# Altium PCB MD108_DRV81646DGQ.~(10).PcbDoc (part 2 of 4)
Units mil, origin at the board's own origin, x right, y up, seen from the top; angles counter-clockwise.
Board outline 6002 x 2931.52 mil, 4 copper layers (Top Layer, Mid-Layer 1, Mid-Layer 2, Bottom Layer), stack 92.712 mil thick; 255 components, 141 nets, 784 pads, 239 vias.
Unrouted connection lines stored in the file: 111.

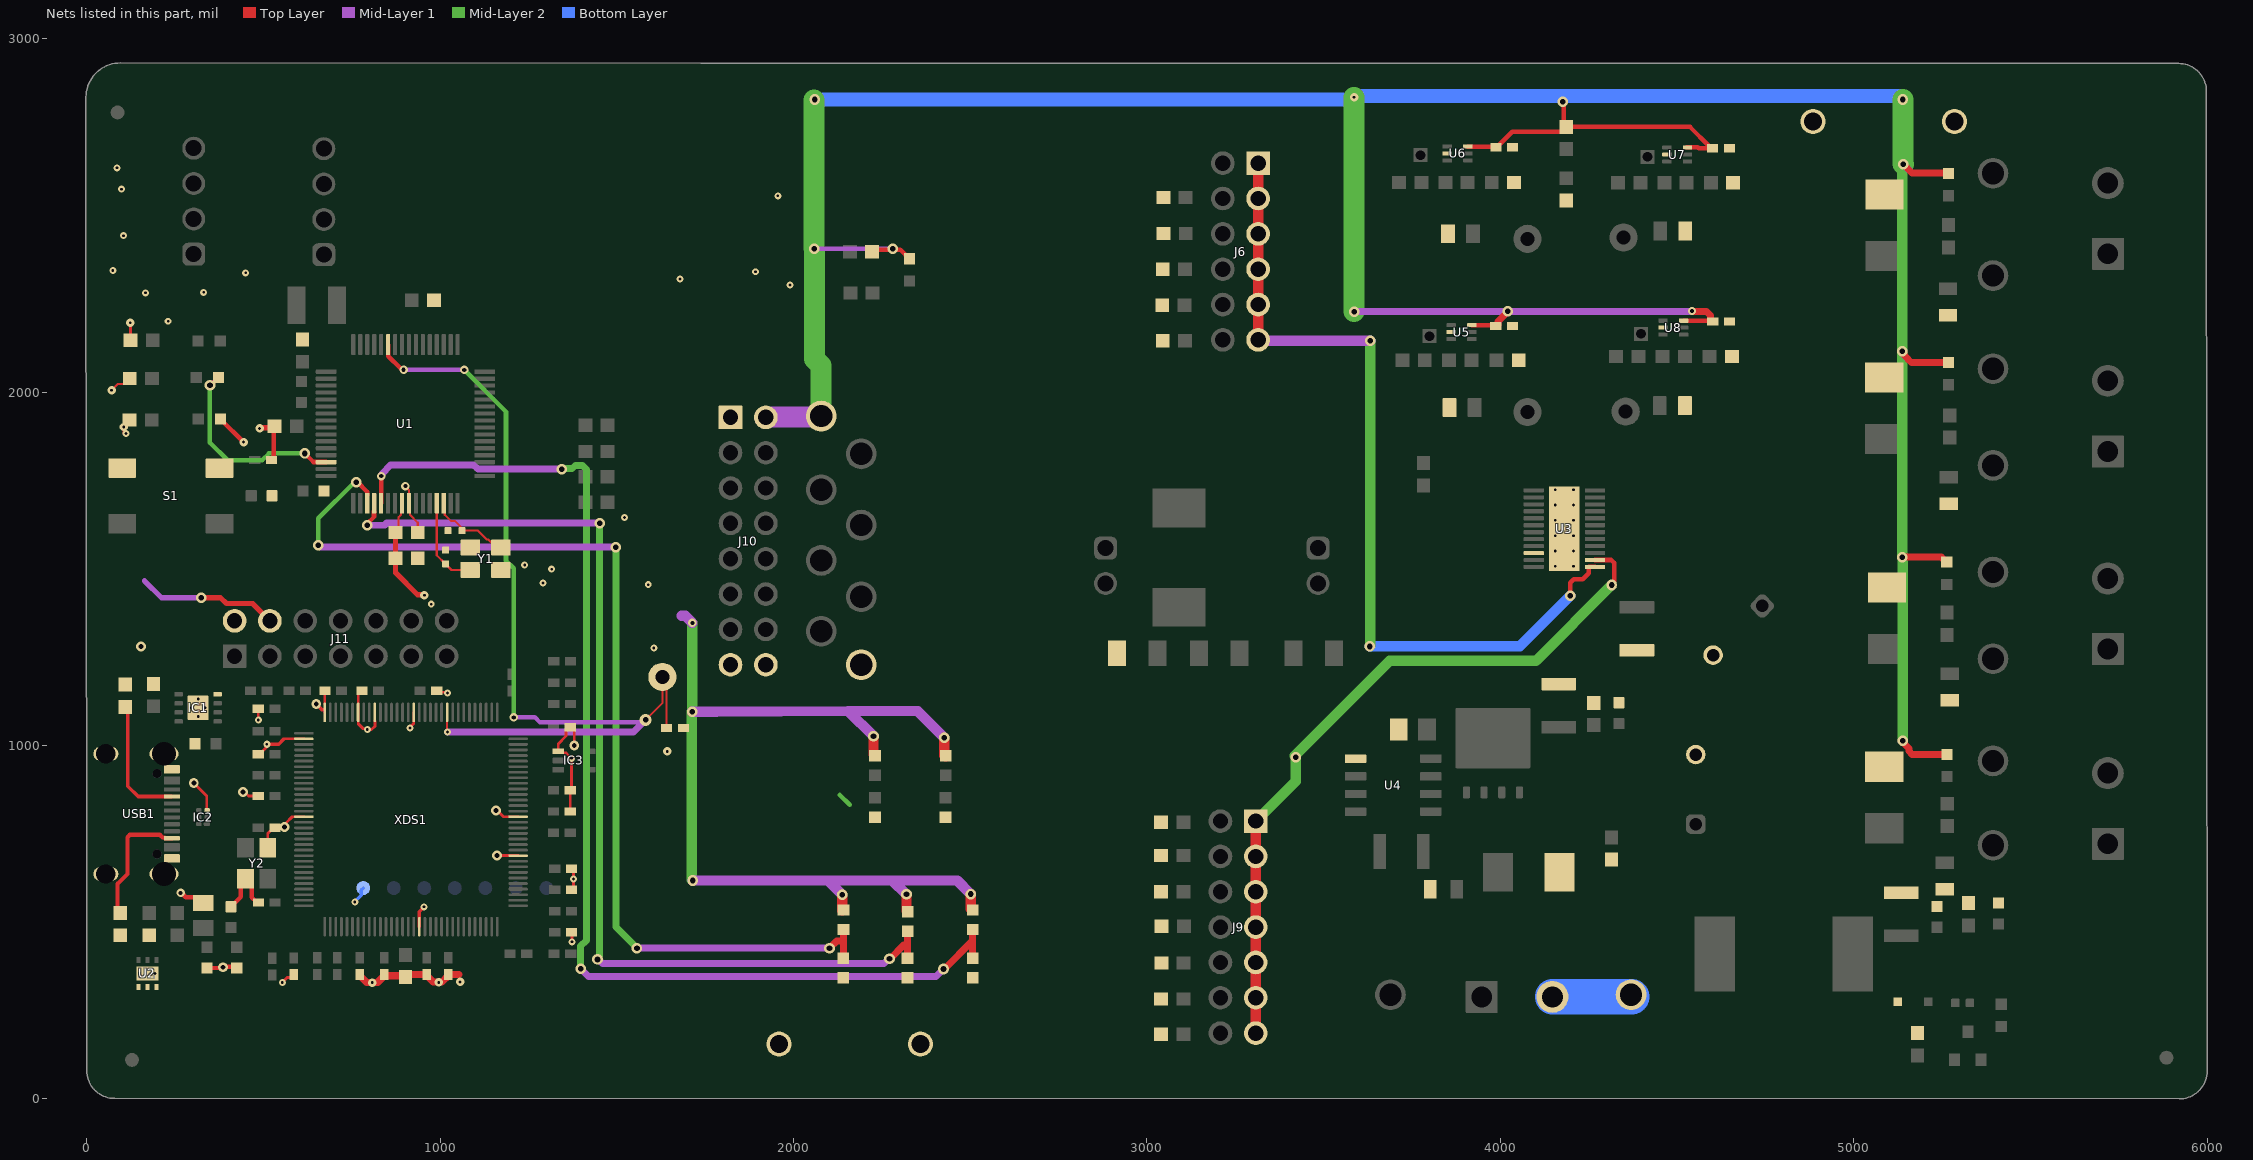
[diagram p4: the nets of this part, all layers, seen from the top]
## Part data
C1: library part CMP-0120896-1, "1 µF ±10% 50V Ceramic Capacitor X7R 0603 (1608 Metric)", Digikey Part Number=732-885012206126CT-ND, Manufacturer="Wurth Electronics", Mouser Part Number=710-885012206126, Operating Temperature Range="-55°C to +125°C", TempCo=15%, Temperature Characteristic=X7R, Tolerance_%=10%, ValueDisplayed=1uF
C2: library part CMP-0120893-1, "10000 pF ±10% 25V Ceramic Capacitor X7R 0603 (1608 Metric)", Digikey Part Number=732-7983-1-ND, Manufacturer="Wurth Electronics", Mouser Part Number=710-885012206065, Operating Temperature Range="-55°C to +125°C", TempCo=15%, Temperature Characteristic=X7R, Tolerance_%=10%, ValueDisplayed=10nF
C3: library part CMP-0119380-1, "WCAP-CSGP Multilayer Ceramic Chip Capacitor, General Purpose, size 0603, X7R Class II, 470nF, 25VDC", Capacitance Tolerance=+/-10%, Case/Size Code=0603, Insulation Resistance=1.1GOhm, Manufacturer="Wurth Elektronik", Operating Temperature Max=125°C, Operating Temperature Min=-55°C, Rated Voltage (DC)=25V
C4: library part CMP-0006837-4, "CAP, CERM, 0.1 uF, 50 V, +/- 10%, X7R, 0603", Cap_Case=0603, Manufacturer="Wurth Elektronik", TempCo=X7R, Tolerance_%=10%, Value1=Unknown, Value2=50V, ValueDisplayed=0.1uF
C5: library part CMP-0860569-1, "CAP, CERM, 10 µF, 25 V,+/- 10%, X5R, 0603", Cap_Case=0603, Manufacturer=MuRata, TempCo=X5R, Tolerance_%=10%, Value2=25V, ValueDisplayed=10µF
C6 C7: library part CMP-0120892-1, "22 pF ±5% 50V Ceramic Capacitor C0G, NP0 0402 (1005 Metric)", Digikey Part Number=732-7471-1-ND, Manufacturer="Wurth Electronics", Mouser Part Number=710-885012005057, Operating Temperature Range="-55°C to +125°C", TempCo=30ppm/°C, Temperature Characteristic=NP0, Tolerance_%=5%, ValueDisplayed=22pF
C8 C12 C17 C20 C24 C25 C28: library part CMP-0006623-2, "CAP, CERM, 0.1 uF, 6.3 V, +/- 10%, X7R, 0402", Cap_Case=0402, Manufacturer=MuRata, Supplier Part Number 1=GRM155R70J104KA01D-ND, TempCo=X7R, Tolerance_%=10%, Value1=Unknown, Value2=6.3V, ValueDisplayed=0.1uF
C9 C10 C11 C15 C18: library part CMP-0006658-2, "CAP, CERM, 0.01 uF, 25 V, +/- 10%, X7R, 0402", Cap_Case=0402, Manufacturer=MuRata, Supplier Part Number 1=490-1312-1-ND, TempCo=X7R, Tolerance_%=10%, Value1=Unknown, Value2=25V, ValueDisplayed=0.01uF
C13: library part CMP-0006831-4, "CAP, CERM, 1 uF, 16 V, +/- 10%, X7R, 0603", Cap_Case=0603, Manufacturer="Wurth Elektronik", Supplier Part Number 1=710-885012206052, TempCo=X7R, Tolerance_%=10%, Value1=Unknown, Value2=16V, ValueDisplayed=1uF
C14: library part CMP-0078154-1, "CAP, CERM, 10 µF, 16 V,+/- 20%, X5R, 0805", Cap_Case=0805, Manufacturer="Wurth Elektronik", Supplier Part Number 1=732-7624-1-ND, TempCo=X5R, Tolerance_%=20%, Value2=16V, ValueDisplayed=10µF
C16 C23: library part CMP-0006415-2, "CAP, CERM, 12 pF, 50 V, +/- 5%, C0G/NP0, 0402", Cap_Case=0402, Manufacturer=MuRata, Supplier Part Number 1=14T3292, TempCo=C0G/NP0, Tolerance_%=5%, Value1=Unknown, Value2=50V, ValueDisplayed=12pF
C19 C26 C29: library part CMP-0006276-2, "CAP, CERM, 1 uF, 25 V, +/- 10%, X5R, 0402", Cap_Case=0402, Manufacturer=TDK, Supplier Part Number 1=445-9066-1-ND, TempCo=X5R, Tolerance_%=10%, Value1=Unknown, Value2=25V, ValueDisplayed=1uF
C21: library part CMP-0750039-1, "CAP, CERM, 0.01 µF, 50 V,+/- 10%, X7R, 0603", Cap_Case=0603, Manufacturer="Wurth Elektronik", TempCo=X7R, Tolerance_%=10%, Value2=50V, ValueDisplayed=0.01µF
C22: library part CMP-0049204-1, "0.1 µF ±10% 50V Ceramic Capacitor X7R 0603 (1608 Metric)", Digikey Part Number=732-8013-1-ND, Manufacturer=Wurth, Mouser Part Number=710-885012206095, Operating Temperature Range="-55°C to +125°C", TempCo=15%, Temperature Characteristic=X7R, Tolerance_%=10%, ValueDisplayed=100nF
C27: library part CMP-0006906-5, "CAP, CERM, 2.2 uF, 10 V, +/- 10%, X5R, 0603", Cap_Case=0603, Manufacturer=Kemet, Supplier Part Number 1=399-4911-1-ND, TempCo=X5R, Tolerance_%=10%, Value1=Unknown, Value2=10V, ValueDisplayed=2.2uF
C30: library part CMP-0119330-1, "WCAP-CSGP Multilayer Ceramic Chip Capacitor, General Purpose, size 0603, X7R, 2.2µF, 10VDC", Capacitance Tolerance=+/-10%, Case/Size Code=0603, Insulation Resistance=0.02GOhm, Manufacturer="Wurth Elektronik", Operating Temperature Max=125°C, Operating Temperature Min=-55°C, Rated Voltage (DC)=10V
C31 C33 C35 C37: library part CMP-0006829-4, "CAP, CERM, 0.1 uF, 16 V, +/- 10%, X7R, 0603", Cap_Case=0603, Manufacturer="Wurth Elektronik", Supplier Part Number 1=710-885012206046, TempCo=X7R, Tolerance_%=10%, Value1=Unknown, Value2=16V, ValueDisplayed=0.1uF
C32 C34 C36 C38: library part CMP-0006219-2, "CAP, CERM, 0.1 uF, 6.3 V, +/- 20%, X5R, 0402", Cap_Case=0402, Manufacturer="Wurth Elektronik", Supplier Part Number 1=732-7478-1-ND, TempCo=X5R, Tolerance_%=20%, Value1=Unknown, Value2=6.3V, ValueDisplayed=0.1uF
C39: library part CMP-0102580-1, "WCAP-ATUL Aluminum Electrolytic Capacitor, Radial, THT, D10 x H12.5mm, 47µF, 100V", Capacitance Tolerance=20%, Leakage Current=47uA, Manufacturer="Wurth Elektronik", Operating Temperature Max=105°C, Operating Temperature Min=-40°C, Rated Voltage (DC)=100V, Ripple Current=400mA
C40 C41 C46: library part CMP-0097312-1, "1 µF ±10% 100V Ceramic Capacitor X7R 1210 (3225 Metric)", Manufacturer="Wurth Electronics", Operating Temperature Range="-55°C to +125°C", TempCo=15%, Temperature Characteristic=X7R, Tolerance_%=10%, ValueDisplayed=1uF
C42 C48: library part CMP-0079993-1, "CAP, CERM, 0.01 µF, 100 V,+/- 10%, X7R, 0603", Cap_Case=0603, Manufacturer="Wurth Elektronik", Supplier Part Number 1=45AC8565, TempCo=X7R, Tolerance_%=10%, Value2=100V, ValueDisplayed=0.01µF
C43: library part CMP-0102582-1, "WCAP-ATUL Aluminum Electrolytic Capacitor, Radial, THT, D10 x H20mm, 82µF, 100V", Capacitance Tolerance=20%, Leakage Current=82uA, Manufacturer="Wurth Elektronik", Operating Temperature Max=105°C, Operating Temperature Min=-40°C, Rated Voltage (DC)=100V, Ripple Current=600mA
C44 C49: library part CMP-0097294-1, "0.1 µF ±10% 100V Ceramic Capacitor X7R 0603 (1608 Metric)", Digikey Part Number=732-885012206120TR-ND, Manufacturer="Wurth Electronics", Mouser Part Number=710-885012206120, Operating Temperature Range="-55°C to +125°C", TempCo=15%, Temperature Characteristic=X7R, Tolerance_%=10%, ValueDisplayed=100nF
C45: library part CMP-0006724-5, "CAP, CERM, 1000 pF, 100 V, +/- 10%, X7R, 0603", Cap_Case=0603, Manufacturer=AVX, Supplier Part Number 1=478-1199-1-ND, TempCo=X7R, Tolerance_%=10%, Value1="0.276 ohm", Value2=100V, ValueDisplayed=1000pF
C47 C53 C54 C55 C56: library part CMP-0119538-1, "WCAP-CSGP Multilayer Ceramic Chip Capacitor, General Purpose, size 0805, X7R, 22nF, 100VDC", Capacitance Tolerance=+/-10%, Case/Size Code=0805, Insulation Resistance=4.5GOhm, Manufacturer="Wurth Elektronik", Operating Temperature Max=125°C, Operating Temperature Min=-55°C, Rated Voltage (DC)=100V
C50: library part CMP-0119409-1, "WCAP-CSGP Multilayer Ceramic Chip Capacitor, General Purpose, size 0603, X7R, 1nF, 100VDC", Capacitance Tolerance=+/-10%, Case/Size Code=0603, Insulation Resistance=10GOhm, Manufacturer="Wurth Elektronik", Operating Temperature Max=125°C, Operating Temperature Min=-55°C, Rated Voltage (DC)=100V
C51: library part CMP-0119921-1, "WCAP-CSST Multilayer Ceramic Chip Capacitor, Soft Termination, size 1210, X7R Class II, 2.2µF, 100VDC", Capacitance Tolerance=+/-10%, Case/Size Code=1210, Insulation Resistance=0.05GOhm, Manufacturer="Wurth Elektronik", Operating Temperature Max=125°C, Operating Temperature Min=-55°C, Rated Voltage (DC)=100V
C52: library part CMP-0007891-2, "CAP, CERM, 1 uF, 100 V, +/- 10%, X7S, 0805", Cap_Case=0805, Manufacturer=TDK, Supplier Part Number 1=445-5205-1-ND, TempCo=X7S, Tolerance_%=10%, Value1="0.008255 ohm", Value2=100V, ValueDisplayed=1uF
D1 D2 D3 D13 D14 D15 D16 D18: library part CMP-0002894-2, "LED, Green, SMD", Color=green, Manufacturer="Wurth Elektronik", Value1=W, Value2=2V
D4: library part CMP-0078131-2, "LED, Red, SMD", Color=Red, Manufacturer=Lite-On, Power_TotalModule=62.5mW, Value1=.0625W, Value2=2V
D5: library part CMP-0002827-3, "LED, Green, SMD", Color=green, Manufacturer=Lite-On, Power_TotalModule=100mW, Value1=0.1W, Value2=2.1V
D6: library part CMP-0002947-3, "LED, Red, SMD", Color=Red, Manufacturer="Wurth Elektronik", Power_TotalModule=72mW, Value1=0.072W, Value2=2V
D7: library part CMP-0005695-3, "Diode, TVS, Bi, 33 V, SMC", Manufacturer=Bourns, Value1=1500W
D8: library part CMP-0005587-3, "Diode, TVS, Bi, 70 V, SMB", Manufacturer="Diodes Inc.", Value1=600W
D9 D10 D11 D12: library part CMP-0005564-3, "Diode, TVS, Bi, 33 V, SMB", Manufacturer="Diodes Inc.", Value1=600W
D17: library part CMP-14400-000003-2, "DIODE ZENER 4.7V 550MW SOD323F"
FID1 FID2 FID3: library part CMP-0077181-1, "Fiducial mark.  There is nothing to buy or mount.", Manufacturer=N/A
IC1: library part CMP-0036329-3, "500mA, Adjustable, Low Quiescent Current, Low-Noise, High-PSRR, Single-Output LDO Regulator, DRB0008A (VSON-8)", Manufacturer="Texas Instruments", Operating Temperature Range="-40 to 125 C", Rating=Catalog
IC2: library part CMP-0043115-3, "4-Channel ESD Protection Array for High-Speed Data Interfaces, DRY0006A (USON-6)", Breakdown Voltage(Min)(V)=6, IO Capacitance(Typ)(pF)=1.6, IO Leakage Current(nA)=1, Manufacturer="Texas Instruments", Operating Temperature Range="-40 to 85 C", Rating=Catalog
IC3: library part CMP-0032790-2, "Precision Micropower Shunt Voltage Reference, 0.5% accuracy, 2.5 V, 15 ppm / degC, 15 mA, -40 to 85 degC, 5-pin SC70 (DCK), Green (RoHS & no Sb/Br)", Manufacturer="Texas Instruments", Rating=Catalog, Temp Coeff(Max)(ppm/ degree C)=100, Temp Coeff(Typ)(ppm/ degree C)=15
J1 J2 J3 J4 J5: library part CMP-0121282-1, "2 Position Wire to Board Terminal Block Horizontal with Board 0.200\" (5.08mm) Through Hole", Current_A=20A, Digikey Part Number=732-10995-ND, Manufacturer="Wurth Electronics", Mouser Part Number=710-691236510002, Operating Temperature Range="-30°C to +120°C", Voltage_V=300V
J6: library part CMP-0092423-1, "THT Vertical Pin Header WR-PHD, Pitch 2.54 mm, Dual Row, 12 pins", Current_A=3A, Digikey Part Number=732-5297-ND, Manufacturer="Wurth Electronics", Mouser Part Number=710-61301221121, Operating Temperature Range="-40°C to +105°C", Voltage_V=250V
J7 J8: library part CMP-0054794-2, "Header, 2.54 mm, 2x1, Gold, TH", Color=Black, Manufacturer="Wurth Elektronik", Supplier Part Number 1=732-5315-ND
J9 J11: library part CMP-0097334-1, "Connector Header Through Hole 14 position 0.100\" (2.54mm)", Current_A=3A, Digikey Part Number=732-5298-ND, Manufacturer="Wurth Electronics", Mouser Part Number=710-61301421121, Operating Temperature Range="-40°C to +105°C", Voltage_V=250V
J10: library part CMP-0125672-1, "Connector Header Through Hole 16 position 0.100\" (2.54mm)", Current_A=3A, Digikey Part Number=732-5299-ND, Manufacturer=Wurth, Mouser Part Number=710-61301621121, Operating Temperature Range="-40°C to +105°C", Voltage_V=250V
J12 J13: library part CMP-0054798-2, "Header, 2.54 mm, 4x1, Gold, TH", Color=Black, Manufacturer="Wurth Elektronik", Supplier Part Number 1=732-5317-ND
L1: library part CMP-0063986-1, "Inductor, Shielded Drum Core, Ferrite, 1 uH, 24 A, 0.0012 ohm, SMD", Manufacturer="Wurth Elektronik", Supplier Part Number 1=732-2138-1-ND, Value1="0.0012 ohm", Value2=24A, ValueDisplayed=1uH
L3: library part CMP-0003267-2, "Ferrite Bead, 600 ohm @ 100 MHz, 0.5 A, 0603", Manufacturer="Wurth Elektronik", Supplier Part Number 1=732-2389-1-ND, Value1="0.35 ohm", Value2=0.5A, ValueDisplayed=600Ω
Logo1: library part CMP-0074844-2, Manufacturer="Texas Instruments"
Logo2: library part CMP-0074838-1, "Texas Instrument Corporate Signature"
Logo3: library part CMP-0074847-1, "FCC_disclaimer"
Logo4: library part CMP-0074769-4, Manufacturer="Texas Instruments"
LOGO5: library part CMP-0074837-2, "IEC 61010-1 Hot Surface Warning", Manufacturer="Texas Instruments"
Logo6: library part CMP-0074836-1, "IEC 61010-1 Caution Warning"
MP1 MP2 MP3 MP4: library part CMP-0122650-1, "Bumper Cylindrical, Dome 0.720\" Dia (18.30mm) Polyurethane Black", Digikey Part Number=RPC4835-ND, Manufacturer="Essentra Components", Mouser Part Number=144-RBS-37BK, Operating Temperature Range="32°F to 122°F"
Q2: library part CMP-1048-00779-1, "General Purpose Transistor, NPN Silicon, 3-Pin SOT-23, Pb-Free, Tape and Reel", Manufacturer="On Semiconductor"
Q4: library part CMP-0000915-2, "MOSFET, N-CH, 80 V, 100 A, DNK0008A (VSON-CLIP-8)", Alternate Manufacturer=None, Manufacturer="Texas Instruments", Supplier Part Number 1=296-37194-1-ND, Value2="48 nC"
R1 R2 R3 R34: library part CMP-0025912-5, "RES, 330, 5%, 0.1 W, 0603", Manufacturer=Yageo, Power_W=100mW, Supplier Part Number 1=311-330GRCT-ND, TempCo="100 ppm/C", Tolerance_%=5%, Value2=0.1W, Value_Code=330R, ValueDisplayed=330
R4: library part CMP-0083496-1, "RES, 20 k, 5%, 0.5 W, 1210", Manufacturer=Yageo, Power_W=500mW, TempCo="100 ppm/C", Tolerance_%=5%, Value2=0.5W, Value_Code=20k0, ValueDisplayed=20k
R5: library part CMP-0025899-5, "RES, 1.0 k, 5%, 0.1 W, 0603", Manufacturer=Yageo, Power_W=100mW, Supplier Part Number 1=311-1.0KGRCT-ND, TempCo="100 ppm/C", Tolerance_%=5%, Value2=0.1W, Value_Code=1k00, ValueDisplayed=1.0k
R6 R7: library part CMP-0025885-5, "RES, 0, 5%, 0.1 W, 0603", Manufacturer=Yageo, PartNumber=RC0603JR-070RL, Power_W=100mW, Supplier Part Number 1=311-0.0GRCT-ND, TempCo="200 ppm/C", Tolerance_%=5%, Value2=0.1W, Value_Code=0000, ValueDisplayed=0
R8 R32: library part CMP-0026935-3, "RES, 47 k, 5%, 0.063 W, AEC-Q200 Grade 0, 0402", Manufacturer=Vishay-Dale, Power_W=63mW, Supplier Part Number 1=541-47KJCT-ND, TempCo="200 ppm/C", Tolerance_%=5%, Value2=0.063W, Value_Code=47k0, ValueDisplayed=47k
R9: library part CMP-0025875-3, "RES, 100 k, 5%, 0.1 W, AEC-Q200 Grade 0, 0603", Manufacturer=Panasonic, Power_W=100mW, Supplier Part Number 1=P100KGCT-ND, TempCo="200 ppm/C", Tolerance_%=5%, Value2=0.1W, Value_Code=100k
R10: library part CMP-0022941-4, "RES, 249 k, 1%, 0.1 W, 0603", Manufacturer=Yageo, Power_W=100mW, Supplier Part Number 1=311-249KHRCT-ND, TempCo="100 ppm/C", Tolerance_%=1%, Value2=0.1W, Value_Code=249k
R11: library part CMP-0023118-5, "RES, 44.2 k, 1%, 0.1 W, 0603", Manufacturer=Yageo, Power_W=100mW, Supplier Part Number 1=311-44.2KHRCT-ND, TempCo="100 ppm/C", Tolerance_%=1%, Value2=0.1W, Value_Code=44k2, ValueDisplayed=44.2k
R12: library part CMP-0022804-5, "RES, 14.0 k, 1%, 0.1 W, 0603", Manufacturer=Yageo, Power_W=100mW, Supplier Part Number 1=311-14.0KHRCT-ND, TempCo="100 ppm/C", Tolerance_%=1%, Value2=0.1W, Value_Code=14k0, ValueDisplayed=14.0k
R13 R23: library part CMP-0025932-5, "RES, 5.1 k, 5%, 0.1 W, 0603", Manufacturer=Yageo, Power_W=100mW, Supplier Part Number 1=311-5.1KGRCT-ND, TempCo="100 ppm/C", Tolerance_%=5%, Value2=0.1W, Value_Code=5k10, ValueDisplayed=5.1k
R14 R25 R26: library part CMP-0026825-5, "RES, 10 k, 5%, 0.063 W, AEC-Q200 Grade 0, 0402", Manufacturer=Vishay-Dale, Power_W=63mW, Supplier Part Number 1=541-10KJCT-ND, TempCo="200 ppm/C", Tolerance_%=5%, Value2=0.063W, Value_Code=10k0, ValueDisplayed=10k
R15 R24: library part CMP-0026824-3, "RES, 100, 5%, 0.063 W, AEC-Q200 Grade 0, 0402", Manufacturer=Vishay-Dale, Power_W=63mW, Supplier Part Number 1=541-100JCT-ND, TempCo="200 ppm/C", Tolerance_%=5%, Value2=0.063W, Value_Code=100R, ValueDisplayed=100
R16: library part CMP-0026413-2, "RES, 4.87 k, 1%, 0.063 W, AEC-Q200 Grade 0, 0402", Manufacturer=Vishay-Dale, Power_W=63mW, Supplier Part Number 1=541-4.87KLCT-ND, TempCo="100 ppm/C", Tolerance_%=1%, Value2=0.063W, Value_Code=4k87, ValueDisplayed=4.87k
R17: library part CMP-0026695-1, "RES, 3.30 k, 1%, 0.1 W, AEC-Q200 Grade 0, 0402", Manufacturer=Panasonic, Power_W=100mW, Supplier Part Number 1=P3.30KLCT-ND, TempCo="100 ppm/C", Tolerance_%=1%, Value2=0.1W, Value_Code=3k30, ValueDisplayed=3.30k
R18 R19 R20 R21 R28: library part CMP-0026852-3, "RES, 1.0 k, 5%, 0.063 W, AEC-Q200 Grade 0, 0402", Manufacturer=Vishay-Dale, Power_W=63mW, Supplier Part Number 1=541-1.0KJCT-ND, TempCo="200 ppm/C", Tolerance_%=5%, Value2=0.063W, Value_Code=1k00, ValueDisplayed=1.0k
R22: library part CMP-0026946-3, "RES, 51, 5%, 0.063 W, AEC-Q200 Grade 0, 0402", Manufacturer=Vishay-Dale, Power_W=63mW, Supplier Part Number 1=541-51JCT-ND, TempCo="200 ppm/C", Tolerance_%=5%, Value2=0.063W, Value_Code=51R0, ValueDisplayed=51
R27 R31: library part CMP-0026934-3, "RES, 470, 5%, 0.063 W, AEC-Q200 Grade 0, 0402", Manufacturer=Vishay-Dale, Power_W=63mW, Supplier Part Number 1=541-470JCT-ND, TempCo="200 ppm/C", Tolerance_%=5%, Value2=0.063W, Value_Code=470R, ValueDisplayed=470
R29: library part CMP-0026731-1, "RES, 330 k, 1%, 0.0625 W, 0402", Manufacturer="Yageo America", Power_W=62.5mW, Supplier Part Number 1=311-330KLRCT-ND, TempCo="100 ppm/C", Tolerance_%=1%, Value2=0.0625W, Value_Code=330k
R30: library part CMP-0026728-1, "RES, 220 k, 1%, 0.0625 W, 0402", Manufacturer="Yageo America", Power_W=62.5mW, Supplier Part Number 1=311-220KLRCT-ND, TempCo="100 ppm/C", Tolerance_%=1%, Value2=0.0625W, Value_Code=220k
R33: library part CMP-0023155-5, "RES, 4.99 k, 1%, 0.1 W, 0603", Manufacturer=Yageo, Power_W=100mW, Supplier Part Number 1=311-4.99KHRCT-ND, TempCo="100 ppm/C", Tolerance_%=1%, Value2=0.1W, Value_Code=4k99, ValueDisplayed=4.99k
R35 R36 R37 R38 R39 R40 R41 R42 R43 R44: library part CMP-0025886-5, "RES, 10 k, 5%, 0.1 W, 0603", Manufacturer=Yageo, Power_W=100mW, Supplier Part Number 1=311-10KGRCT-ND, TempCo="100 ppm/C", Tolerance_%=5%, Value2=0.1W, Value_Code=10k0, ValueDisplayed=10k
R45 R53 R74: library part CMP-0022746-5, "RES, 10.0 k, 1%, 0.1 W, 0603", Manufacturer=Yageo, Power_W=100mW, Supplier Part Number 1=311-10.0KHRCT-ND, TempCo="100 ppm/C", Tolerance_%=1%, Value2=0.1W, Value_Code=10k0, ValueDisplayed=10.0k
R46 R56: library part CMP-0023212-5, "RES, 60.4 k, 1%, 0.1 W, 0603", Manufacturer=Yageo, Power_W=100mW, Supplier Part Number 1=311-60.4KHRCT-ND, TempCo="100 ppm/C", Tolerance_%=1%, Value2=0.1W, Value_Code=60k4, ValueDisplayed=60.4k
R47 R58: library part CMP-0022768-4, "RES, 120 k, 1%, 0.1 W, 0603", Manufacturer=Yageo, Power_W=100mW, Supplier Part Number 1=311-120KHRCT-ND, TempCo="100 ppm/C", Tolerance_%=1%, Value2=0.1W, Value_Code=120k
R48: library part CMP-0022844-4, "RES, 180 k, 1%, 0.1 W, 0603", Manufacturer=Yageo, Power_W=100mW, Supplier Part Number 1=311-180KHRCT-ND, TempCo="100 ppm/C", Tolerance_%=1%, Value2=0.1W, Value_Code=180k
R49 R59: library part CMP-0022937-4, "RES, 240 k, 1%, 0.1 W, 0603", Manufacturer=Yageo, Power_W=100mW, Supplier Part Number 1=311-240KHRCT-ND, TempCo="100 ppm/C", Tolerance_%=1%, Value2=0.1W, Value_Code=240k
R50 R51 R52: library part CMP-0086176-1, "RES, 0, 0.75 W, AEC-Q200 Grade 0, 1206", Manufacturer=Vishay-Dale, Power_W=750mW, Tolerance_%=0%, Value2=0.75W, Value_Code=0
R54: library part CMP-0023020-5, "RES, 30.0 k, 1%, 0.1 W, 0603", Manufacturer=Yageo, Power_W=100mW, Supplier Part Number 1=311-30.0KHRCT-ND, TempCo="100 ppm/C", Tolerance_%=1%, Value2=0.1W, Value_Code=30k0, ValueDisplayed=30.0k
R55: library part CMP-0023098-5, "RES, 40.2 k, 1%, 0.1 W, 0603", Manufacturer=Yageo, Power_W=100mW, Supplier Part Number 1=311-40.2KHRCT-ND, TempCo="100 ppm/C", Tolerance_%=1%, Value2=0.1W, Value_Code=40k2, ValueDisplayed=40.2k
R57: library part CMP-0023285-5, "RES, 80.6 k, 1%, 0.1 W, 0603", Manufacturer=Yageo, Power_W=100mW, Supplier Part Number 1=311-80.6KHRCT-ND, TempCo="100 ppm/C", Tolerance_%=1%, Value2=0.1W, Value_Code=80k6, ValueDisplayed=80.6k
R60 R61 R65 R66 R68 R69 R71 R72: library part CMP-0025874-4, "RES, 0, 5%, 0.1 W, AEC-Q200 Grade 0, 0603", Manufacturer=Panasonic, Power_W=100mW, Supplier Part Number 1=P0.0GCT-ND, TempCo="600 ppm/C", Tolerance_%=5%, Value2=0.1W, Value_Code=0000, ValueDisplayed=0
R62 R67 R70 R73: library part CMP-0041688-1, "10 mOhms ±1% 0.5W, 1/2W Chip Resistor 0805 (2012 Metric) Current Sense Thick Film", Digikey Part Number=732-13830-1-ND, Manufacturer="Wurth Electronics", Mouser Part Number=710-580060720008, Operating Temperature Range="-55°C to +155°C", Power_W=500mW, TempCo=100ppm/°C, Tolerance_%=1%
R63 R64: library part CMP-0022902-5, "RES, 200, 1%, 0.1 W, 0603", Manufacturer=Yageo, Power_W=100mW, Supplier Part Number 1=311-200HRCT-ND, TempCo="100 ppm/C", Tolerance_%=1%, Value2=0.1W, Value_Code=200R, ValueDisplayed=200
R77 R78 R79 R80: library part CMP-0025922-5, "RES, 430, 5%, 0.1 W, 0603", Manufacturer=Yageo, Power_W=100mW, Supplier Part Number 1=311-430GRCT-ND, TempCo="100 ppm/C", Tolerance_%=5%, Value2=0.1W, Value_Code=430R, ValueDisplayed=430
R81: library part CMP-0097568-1, "47 kOhms ±1% 0.125W, 1/8W Chip Resistor 0402 (1005 Metric) Automotive AEC-Q200 Thick Film", Digikey Part Number=541-RCC040247K0FKEDCT-ND, Manufacturer="Vishay Dale", Mouser Part Number=71-RCC040247K0FKED, Operating Temperature Range="-55°C to +155°C", Power_W=125mW, TempCo=100ppm/°C, Tolerance_%=1%
R82: library part CMP-0023129-5, "RES, 470, 1%, 0.1 W, 0603", Manufacturer=Yageo, Power_W=100mW, Supplier Part Number 1=311-470HRCT-ND, TempCo="100 ppm/C", Tolerance_%=1%, Value2=0.1W, Value_Code=470R, ValueDisplayed=470
S1: library part CMP-0097347-1, "Tactile Switch SPST-NO Top Actuated Surface Mount", Coil Resistance_ohm=100mΩ, Contact Current Rating=50mA, Digikey Part Number=732-7022-1-ND, Manufacturer="Wurth Electronics", Mouser Part Number=710-430481025816, Operating Force=160gf, Operating Temperature Range="-40°C to +85°C"
SH1 SH2: library part CMP-0075110-1, "1mm Uninsulated Shorting Plug, 10.16mm spacing, TH", Manufacturer=Harwin, PartNumber=D3082-05, Supplier Part Number 1=952-1873-ND
SH-J1 SH-J2 SH-J3 SH-J4 SH-J5 SH-J6 SH-J7 SH-J8 SH-J9 SH-J10 SH-J11 SH-J12 SH-J14 SH-J15 SH-J16 SH-J17 SH-J18 SH-J19 SH-J20: library part CMP-0003761-2, "Shunt, 2.54mm, Gold, Black", Manufacturer="Wurth Elektronik", Supplier Part Number 1=732-2678-ND
TP1 TP2 TP3 TP4 TP5 TP6 TP7: library part CMP-0003825-1, "1mm Test Point, SMT", Manufacturer=Any, PartNumber=TP_SM_1MM
TP8 TP24 TP27 TP28 TP29: library part CMP-0055139-2, "Test Point, Miniature, White, TH", Color=White, Manufacturer="Keystone Electronics", Supplier Part Number 1=36-5002-ND
TP9 TP11 TP12 TP13 TP14 TP15 TP17 TP18 TP19 TP22: library part CMP-0055149-2, "Test Point, Multipurpose, White, TH", Color=White, Manufacturer="Keystone Electronics", Supplier Part Number 1=36-5012-ND
TP10: library part CMP-0055150-1, "Test Point, Multipurpose, Orange, TH", Color=Orange, Manufacturer=Keystone, Supplier Part Number 1=36-5013-ND
TP16 TP21 TP23 TP31 TP32: library part CMP-0055147-2, "Test Point, Multipurpose, Red, TH", Color=Red, Manufacturer="Keystone Electronics", Supplier Part Number 1=36-5010-ND
TP25: library part CMP-0055148-2, "Test Point, Multipurpose, Black, TH", Color=Black, Manufacturer="Keystone Electronics", Supplier Part Number 1=36-5011-ND
TP33: library part CMP-0055148-1, "Test Point, Multipurpose, Black, TH", Color=Black, Manufacturer=Keystone, Supplier Part Number 1=36-5011-ND
U1: library part CMP-0093960-1, "Mixed-Signal Microcontrollers With CAN-FD Interface LQFP64", Frequency_Fixed=80MHz, Manufacturer="Texas Instruments", Max Supply Voltage=3.6V, Min Supply Voltage=1.62V, Operating Temperature Range="-40°C to +125°C"
U2: library part CMP-0077837-1, "5-V Precision Surge Protection Clamp, DRV0006A (WSON-6)", Alternate Manufacturer="Texas Instruments"
U3: library part CMP-0125014-1, "Quad Low-Side Switches, HVSSOP24", Manufacturer="Texas Instruments", Max Supply Voltage=65V, Min Supply Voltage=4.5V, Nominal Supply Current=3mA, Operating Temperature Range="-40°C to +150°C"
U4: library part CMP-0125797-1, Manufacturer="Texas Instruments", Operating Temperature Range=to
U5 U6 U7 U8: library part CMP-0085241-1, "Bidirectional, Precision Low- and High-Side Voltage Output, Current-Sense Amplifier, DRL0006A (SOT-5X3-6)", Alternate Manufacturer="Texas Instruments", Alternate PartNumber=INA185A2IDRLR
USB1: library part CMP-0095999-2, "Conenctor USB 2.0 Type C Horizontal SMT", Current_A=5A, Manufacturer="Wurth Electronics", Operating Temperature Range="-40°C to +85°C", Voltage_V=20V
XDS1: library part CMP-0077954-1, "MSP432E401YTPDT, PDT0128A (TQFP-128)", Alternate Manufacturer="Texas Instruments", Alternate PartNumber=MSP432E401YTPDT
Y1: library part CMP-0098168-2, "Crystal 40MHz ±10ppm (Tol) ±20ppm (Stability) 12pF FUND 40Ohm 4-Pin Mini-CSMD T/R", Frequency Stability=20ppm, Frequency Tolerance=10ppm, Frequency_Fixed=40MHz, Load Capacitance=12pF, Manufacturer="Seiko Epson", Operating Temperature Range="-40°C to +105°C"
Y2: library part CMP-0004635-3, "Crystal, 16 MHz, 8pF, SMD", Frequency Stability=+/-30ppm, Frequency_Fixed=16MHz, Manufacturer=NDK, Supplier Part Number 1=644-1157-1-ND
ZZ1: library part CMP-0003616-3
ZZ2: library part CMP-0077236-1
ZZ3: library part CMP-0077237-1
ZZ4: library part CMP-0077238-1

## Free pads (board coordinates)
  rect 39.37x39.37 hole 27.56: 3(4398.45,2164.95) 7(3773.88,2670.35) 7(3799.96,2158.3) 7(4416.63,2665.76)

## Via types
v1: diameter 30, hole 16, Top Layer to Bottom Layer, tented both sides, 89 vias
v2: diameter 20, hole 8, Top Layer to Bottom Layer, tented both sides, 47 vias
v3: diameter 19.68, hole 7.87, Top Layer to Bottom Layer, tented both sides, 35 vias
v4: diameter 24, hole 12, Top Layer to Bottom Layer, tented both sides, 14 vias
v5: diameter 24, hole 7.87, Top Layer to Bottom Layer, tented both sides, 11 vias
v6: diameter 30, hole 15, Top Layer to Bottom Layer, tented both sides, 10 vias
v7: diameter 28, hole 14, Top Layer to Bottom Layer, tented both sides, 9 vias
v8: diameter 19.68, hole 7.87, Top Layer to Bottom Layer, 6 vias
v9: diameter 24, hole 8, Top Layer to Bottom Layer, tented both sides, 5 vias
v10: diameter 30, hole 14, Top Layer to Bottom Layer, tented both sides, 4 vias
v11: diameter 24, hole 11.81, Top Layer to Bottom Layer, tented both sides, 4 vias
v12: diameter 36, hole 18.29, Top Layer to Bottom Layer, tented both sides, 2 vias
v13: diameter 30, hole 15.75, Top Layer to Bottom Layer, tented both sides, 2 vias
v14: diameter 34, hole 16, Top Layer to Bottom Layer, tented both sides, 1 vias

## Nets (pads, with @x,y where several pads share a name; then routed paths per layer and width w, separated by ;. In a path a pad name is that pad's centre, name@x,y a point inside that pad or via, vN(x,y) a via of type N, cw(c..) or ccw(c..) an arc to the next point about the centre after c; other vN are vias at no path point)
3V3: C32.2 C34.2 C36.2 C38.2 D6.2 D13.2 D14.2 D15.2 D16.2 J10.2 R33.2 R63.2 TP10.1 U5.6 U6.6 U7.6 U8.6 | length 9611.1
  Top Layer w12.83: R33.2@2215.65,2401.97 2216.41,2402.74 2277.57,2402.74 v1(2280.86,2406.02) 2284.14,2402.74 2302.6,2402.74 2327.64,2377.69 D6.2@2331.23,2377.69 ; U6.6@3908.06,2694.9 3908.57,2694.38 C32.2@3983.59,2694.38 ; U5.6@3919.44,2189.5 3919.95,2188.99 C36.2@3985.12,2188.99 ; C32.2@3983.59,2694.58 3993.41,2694.58 3996.77,2697.94 3996.77,2699.76 4034.07,2737.06 4174.21,2737.06 4186.49,2749.34 R63.2@4186.49,2750.33 4536.98,2750.33 4591.53,2695.77 4591.53,2694.96 C34.2@4596.93,2689.56 ; v1(4176.98,2822.09) 4179.12,2819.95 R63.2@4179.12,2756.36 ; U8.6@4518.83,2202.04 4519.35,2201.53 C38.2@4593.47,2201.53 ; U7.6@4528.09,2692.81 4558.19,2692.81 4561.44,2689.56 C34.2@4596.93,2689.56 ; C34.2@4604.01,2687.37 4599.13,2687.37 C34.2@4596.93,2689.56
  Top Layer w19.68: C36.2@3986.25,2187.33 3991.1,2187.33 3992.9,2189.13 3992.9,2199.38 4020.71,2227.18 v1(4020.71,2228.35) ; v4(4542.46,2229.48) 4543.29,2228.65 4583.66,2228.65 4595.19,2217.12 4595.19,2201.66 4597.16,2199.69 C38.2@4601.09,2199.69 ; v1(5137.37,2115.28) 5137.37,2110.61 5154.18,2093.8 5154.18,2092.86 5163.19,2083.85 D14.2@5268.21,2083.85 ; v1(5137.66,1532.96) 5247.87,1532.96 5252.59,1528.25 5254.12,1528.25 5261.97,1520.4 D15.2@5261.97,1518.87 ; v1(5138.92,1013.35) 5138.92,1008.71 5156.17,991.46 5156.17,984.09 5165.25,975.01 D16.2@5264.42,975.01 ; v1(5140.47,2644.7) 5165.42,2619.76 5265.14,2619.76 D13.2@5266.14,2620.76
  Top Layer w59.06: J10.2@1918.99,1928.64 1920.52,1928.64 J10.2@1922.46,1926.71
  Mid-Layer 1 w12.83: v1(2058.25,2406.02) v1(2280.86,2406.02)
  Mid-Layer 1 w19.68: v1(3586.44,2227.8) 3586.71,2228.07 v1@4019.12,2228.07 ; v1(4020.71,2228.35) 4541.33,2228.35 v4(4542.46,2229.48)
  Mid-Layer 1 w59.06: J10.2@1918.99,1928.64 1920.36,1930.01 2076.04,1930.01 TP10.1@2078.24,1932.21
  Mid-Layer 2 w29.53: v1(5138.92,1013.35) 5138.92,1531.57 5137.66,1532.84 5137.66,2114.86 5137.37,2115.15 5137.37,2641.47 5140.47,2644.57 v1(5140.47,2644.7)
  Mid-Layer 2 w59.06: v1@2057.96,2826.86 2058.25,2826.57 v1(2058.25,2406.02) 2059.56,2404.71 2059.56,2093.82 2078.24,2075.14 TP10.1@2078.24,1932.21 ; v1(3586.44,2227.8) v9(3586.44,2834.36) ; v1(5139.28,2828.08) 5139.28,2645.9 v1(5140.47,2644.7)
  Bottom Layer w19.68: v1(3586.44,2227.8) v1@3586.71,2228.07 ; v1@4020.44,2228.07 v1(4020.71,2228.35)
  Bottom Layer w39.37: v1(2060.1,2828.08) 3580.16,2828.08 v9(3586.44,2834.36) ; v9@3586.44,2837.84 5129.52,2837.84 v1(5139.28,2828.08)
3V3_MCU: C4.1 C5.1 D3.2 J10.1 J11.4 R7.1 R8.2 R35.1 R37.1 R39.1 R41.1 R43.1 U1.40 | length 3720
  Top Layer w6: C4.1@873.83,1602.89 882.61,1611.68 882.61,1646.01 889.31,1652.7 889.31,1655.55 889.31,1682.69 U1.40@892.21,1685.59
  Top Layer w12.83: D3.2@378.52,1923.54 444.42,1857.63 v5@444.42,1857.37 ; R8.2@522.58,1808.03 523.69,1808.03 529.09,1813.43 R7.1@529.09,1902.65
  Top Layer w15: v6(323.86,1418.2) 378.73,1418.2 395.36,1401.57 469.61,1401.57 J11.4@518.44,1352.72 ; v5(489.23,1897.18) 490.95,1898.9 525.1,1898.9 R7.1@528.85,1902.65 ; C4.1@873.83,1602.89 873.83,1489.04 936.15,1426.72 953.88,1426.72 v5(955.6,1425)
  Top Layer w29.53: v1(2137.5,577.9) 2138.38,577.03 R39.1@2138.38,534.3 ; v1(2226.44,1026.09) 2226.44,975.52 R35.1@2228.19,973.77 ; R41.1@2319.74,532.56 v1(2319.74,578.77) ; v1(2427,1021.73) 2427,972.9 R37.1@2430.48,969.41 ; v1(2501.99,579.64) 2501.99,537.79 R43.1@2504.6,535.17
  Mid-Layer 1 w15: 163.76,1465.84 211.39,1418.2 v6(323.86,1418.2)
  Mid-Layer 1 w29.53: 1684.15,1367.17 1693.49,1367.17 v11(1713.95,1346.71) ; v1(1713.71,1095.38) 1781.13,1095.38 1781.7,1095.95 2154.94,1097.59 ; v1(1714.6,618.01) 2098.27,618.01 ; v1(2137.5,577.9) 2136.63,578.77 2136.63,579.64 2098.27,618.01 ; v1(2226.44,1026.09) 2154.94,1097.59 ; v1(2319.74,578.77) 2318.87,578.77 2279.63,618.01 ; v1(2427,1021.73) 2351.14,1097.59 2154.94,1097.59 ; v1(2501.99,579.64) 2463.62,618.01 2279.63,618.01 ; 2098.27,618.01 2279.63,618.01
  Mid-Layer 2 w29.53: v1@1712.57,1095.38 1712.57,619.46 v1@1714.28,617.74 ; v1(1713.71,1095.38) 1713.71,1346.47 v11(1713.95,1346.71)
  other v5: 443.72,1858.75
+5V: J11.2
BSL_INVOKE: R32.2 TP8.1 U1.11 XDS1.42 | length 2613.7
  Top Layer w6: XDS1.42@1019.98,1093.72 1019.98,1038.93 v3(1020.64,1038.27) ; v14(1581.77,1072.7) 1629,1119.92 TP8.1@1629,1194 1641,1182 R32.2@1641.01,1049.62
  Top Layer w12.83: U1.11@852.84,2134.41 853.35,2133.9 853.35,2101.73 888.29,2066.79 889.78,2066.79 893.51,2063.06 v4(896.54,2063.06)
  Mid-Layer 1 w6: v14@1581.22,1072.14 v14@1581.22,1074.06
  Mid-Layer 1 w12.83: v4(896.54,2063.06) 1068.13,2063.06 v4(1068.32,2062.87) ; v4(1208.2,1079.48) 1268.4,1079.48 1282.73,1065.15 1568.5,1065.15 1580.98,1077.63 v14@1583.08,1077.63
  Mid-Layer 1 w19.68: v3(1020.64,1038.27) 1547.35,1038.27 v14@1581.22,1072.14
  Mid-Layer 2 w12.83: v4(1068.32,2062.87) 1186.44,1944.74 1186.44,1522.99 1208.2,1501.23 v4(1208.2,1079.48)
CC1: R13.1 USB1.A5 | length 364.1
  Top Layer w10: R13.1@108.91,1109.14 116.59,1101.45 116.59,884.67 145.6,855.67 USB1.A5@241.04,855.67
CC2: R23.1 USB1.B5 | length 362.2
  Top Layer w12: R23.1@94.73,526.06 86.91,533.89 86.91,608.51 115.09,636.69 115.09,740.38 122.12,747.41 206.51,747.41 214.57,739.34 220.21,739.34 221.89,737.66 240.94,737.66 USB1.B5@241.04,737.56
COD/INRUSH: J6.1 J6.3 J6.5 J6.7 J6.9 J6.11 U3.13 | length 2454.8
  Top Layer w12.83: v1(4197.75,1423.32) 4197.75,1460.49 4207.86,1470.61 4233.28,1470.61 4250.13,1487.46 4250.13,1504.74 4250.64,1505.25 U3.13@4267.92,1505.25
  Top Layer w29.53: J6.1@3311.87,2655.3 3314.82,2652.34 J6.1@3314.82,2647.78 J6.11@3314.82,2147.78
  Mid-Layer 1 w29.53: J6.11@3314.82,2147.78 3317.02,2145.58 v1(3632.19,2145.58)
  Mid-Layer 2 w29.53: v1(3630.96,1280.32) 3632.19,1281.56 v1(3632.19,2145.58)
  Bottom Layer w29.53: v1(3630.96,1280.32) 4054.75,1280.32 v1(4197.75,1423.32)
DEV_ID1: R39.2 R40.1 U1.35 | length 2948.7
  Top Layer w12.83: v1(762.87,1745.3) 765,1743.16 768.38,1743.16 793.27,1718.27 U1.35@793.27,1708.7
  Top Layer w19.68: v1(2101.99,426.78) 2122.37,447.16 2141.07,447.16 ; R40.1@2139.91,403.7 2141.07,404.87 2141.07,447.16 ; R39.2@2141.22,479.06 2141.07,478.92 2141.07,447.16
  Mid-Layer 1 w19.68: v1(655.45,1566.92) 656.61,1566.92 661.36,1562.17 1496.33,1562.17 v1(1497.14,1561.36) ; v1(1556.99,426.78) v1(2101.99,426.78)
  Mid-Layer 2 w12.83: v1(655.45,1566.92) 655.45,1642.68 756.32,1743.55 761.12,1743.55 v1(762.87,1745.3)
  Mid-Layer 2 w19.68: v1(1497.14,1561.36) 1497.14,486.63 v1(1556.99,426.78)
DEV_ID2: R41.2 R42.1 U1.36 | length 2922.5
  Top Layer w12.83: v1(794.15,1623.23) 794.15,1627.87 812.96,1646.68 U1.36@812.96,1662.48
  Top Layer w19.68: v1(2271.64,396.32) 2273.32,396.32 2313.19,436.19 2323.12,436.19 ; R42.1@2320.74,400.83 2323.12,403.22 2323.12,436.19 ; R41.2@2323.2,474.53 2323.12,474.45 2323.12,436.19
  Mid-Layer 1 w19.68: v1(794.15,1623.23) 842.77,1623.23 848.52,1628.97 1451.24,1628.97 v1(1451.34,1629.07) ; v1(1445.25,394.67) 1448.04,394.67 1459.04,383.68 2256.21,383.68 2268.85,396.32 v1(2271.64,396.32)
  Mid-Layer 2 w19.68: v1(1445.25,394.67) 1445.25,397.46 1451.34,403.55 v1(1451.34,1629.07)
DEV_ID3: R43.2 R44.1 U1.37 | length 3335.6
  Top Layer w12.83: U1.37@833.16,1685.59 v4(833.16,1762.34)
  Top Layer w19.68: v1(2424.34,367.55) 2427.04,367.55 2506.99,447.5 ; R43.2@2506.99,479.06 2506.99,447.5 ; R44.1@2511.41,407.8 2507.51,407.8 2506.99,408.32 2506.99,447.5
  Mid-Layer 1 w19.68: v4@835.1,1768.61 860.02,1793.53 1095.04,1793.53 1106.77,1781.8 v1(1344.58,1781.8) ; v1(1397.67,368.52) 1420.25,345.94 2402.73,345.94 v1(2424.34,367.55)
  Mid-Layer 2 w19.68: v1(1344.58,1781.8) 1346.56,1783.78 1373.81,1783.78 1382.73,1792.7 1402.42,1792.7 1413.95,1781.17 1413.95,448.36 1397.67,432.08 v1(1397.67,368.52)
GND: C2.2 C3.1 C4.2 C5.2 C6.1 C7.1 C8.2 C9.2 C10.2 C11.2 C12.2 C13.2 C14.2 C15.2 C16.2 C17.2 C18.2 C19.2 C20.2 C21.2 C22.2 C23.2 C24.2 C25.2 C26.2 C27.2 C28.2 C29.2 C30.1 C32.1 C34.1 C36.1 C38.1 C39.2 C40.1 C41.1 C42.1 C43.2 C44.1 C45.2 C46.1 C47.1 C48.1 C49.1 C50.1 C52.2 C53.1 C54.1 C55.1 C56.1 D4.2 D5.2 D8.1 D9.1 D10.1 D11.1 D12.1 D17.2 IC1.4 IC1.9 IC2.3 IC3.1 J5.2 J10.15 J10.16 R1.1 R2.1 R3.1 R5.1 R6.1 R13.2 R16.1 R23.2 R30.1 R32.1 R36.2 R38.2 R40.2 R42.2 R44.2 R45.1 R46.1 R47.1 R48.1 R49.1 R50.1 R53.1 R54.1 R55.1 R56.1 R57.1 R58.1 R59.1 R61.1 R62.1 R64.1 R66.1 R67.1 R69.1 R70.1 R72.1 R73.1 R82.1 S1.3 S1.4 SH1.1 SH1.2 SH2.1 SH2.2 TP1.1 TP25.1 TP33.1 U1.41 U2.1 U2.2 U2.3 U2.7@171.8,354.86 U3.10 U3.25 U4.1 U5.2 U6.2 U7.2 U8.2 USB1.1 USB1.2 USB1.3 USB1.4 USB1.A1-B12 USB1.A12-B1 XDS1.10 XDS1.17 XDS1.48 XDS1.55 XDS1.58 XDS1.64 XDS1.66 XDS1.80 XDS1.114 Y1.2 Y1.4 Y2.2 Y2.4 | length 2790
  Top Layer w6: v5(70.4,2005.1) 88.08,2022.78 106.03,2022.78 R2.1@121.73,2038.49 ; v4(901.85,1734.24) 901.85,1732.46 911.9,1722.41 U1.41@911.9,1685.59 914.8,1682.69 914.8,1652.62 936.83,1630.59 C4.2@936.83,1602.89 ; R32.1@1684.32,1049.62 R32.1@1688.25,1049.62
  Top Layer w8: v3@104.72,1883.17 v9(104.72,1901.23) 121.04,1917.55 R3.1@121.04,1921.12 ; R1.1@122.75,2145.6 R1.1@123.8,2146.65 123.51,2146.94 v5(123.51,2196.26) ; v7(303.01,893.72) 339.86,856.88 339.86,820.06 340.3,819.62 IC2.3@338.33,819.62 ; v7(442.61,868.57) 446.24,868.57 457.63,857.18 C15.2@485.37,857.18 ; C8.2@483.18,1103.54 485.61,1101.11 v2(485.61,1072.57) ; C12.2@485.37,975.59 489.31,975.59 507.32,993.6 507.32,1001.27 v2(509.61,1003.57) v2@507.32,1005.86 ; Y2.2@512.19,710.19 512.19,750.75 528.68,767.24 C16.2@532.62,767.24 533.45,768.07 559.19,768.07 v7(560.02,768.9) 563.85,772.72 563.85,780.8 581.49,798.44 XDS1.80@614.46,798.44 ; v2(553.48,329.8) 567.56,343.87 578.02,343.87 585.83,351.68 C24.2@585.83,351.79 ; 557.61,1018.57 557.96,1018.91 XDS1.66@614.46,1018.91 ; XDS1.64@673.52,1093.72 XDS1.64@673.52,1101.49 ; XDS1.64@673.52,1117.28 R16.1@673.52,1154.45 ; C9.2@777.24,1160.69 776.27,1160.69 768.46,1152.88 768.46,1069.64 768.52,1069.58 768.52,1061.66 782.65,1047.53 791.8,1047.53 v2(794.1,1045.23) 794.15,1045.28 806.33,1045.28 815.71,1054.66 815.71,1069.77 XDS1.55@815.32,1070.16 ; v2(914.8,1049.28) 914.8,1051.45 925.49,1062.13 XDS1.48@925.49,1093.72 ; C10.2@990.44,1154.97 994.55,1150.86 1018.32,1150.86 v2(1020.61,1148.57) ; v7@1160.65,688.53 XDS1.10@1221.18,688.53 ; v7@1161.83,815.57 1178.96,798.44 XDS1.17@1220.76,798.44 ; C18.2@1368.35,813.04 C17.2@1368.35,873 1371.81,876.46 v2(1371.81,963.72) 1356.25,979.28 1338.2,979.28 IC3.1@1334.32,983.16 1334.32,1004.24 1356.61,1026.53 1356.61,1043.74 1364.42,1051.55 C11.2@1368.35,1051.55 1371.8,1051.55 1379.61,1043.74 v7(1379.61,1000.57) ; R30.1@1371.81,471.51 1373.61,469.71 v2(1373.61,444.57) ; C20.2@1371.81,591.43 1377.61,597.24 v2(1377.61,622.57) 1377.61,645.58 C19.2@1371.81,651.39
  Top Layer w10: v2(509.61,1003.57) 543.32,1003.57 557.97,1018.21 ; v7(649.61,1117.57) 665.69,1101.49 XDS1.64@672.46,1101.49 ; XDS1.114@941.24,487.42 941.24,529.98 954.61,543.35 v2(954.61,543.57) ; v7(1158.61,815.57) v7@1161.83,815.57
  Top Layer w12: D4.2@344.61,368.07 346.86,370.32 383.37,370.32 v7(385.61,372.57) 387.31,374.26 422.92,374.26 D5.2@424.61,375.96
  Top Layer w12.83: v4(265.77,582.98) 268.79,582.98 280.69,571.08 316.6,571.08 C14.2@328.88,558.79 ; C22.2@408.25,543.9 435.73,571.38 435.73,619.34 Y2.4@444.58,628.19 ; Y2.4@449.2,623.58 466.4,606.37 466.4,571.09 481.8,555.69 C23.2@486.7,555.69
  Top Layer w20: C25.2@773.12,352.34 773.12,348.4 791.64,329.89 807.25,329.89 v9(808.01,329.12) 808.78,329.89 823.49,329.89 842,348.4 C26.2@842,352.34 842,350.21 843.81,348.4 898.41,348.4 C27.2@902.34,344.46 ; C27.2@902.34,352.34 C28.2@962.68,352.34 962.68,348.4 980.52,330.56 995.17,330.56 v9(995.94,329.8) 996.7,330.56 1005.19,330.56 1023.03,348.4 C29.2@1023.03,352.34 1053.13,352.34 1053.89,351.57
  Mid-Layer 2 w12.83: 2131.08,859.9 2158.7,832.28
  Bottom Layer w10: v2(758.61,557.57) 776.99,575.95 776.99,590.95 TP1.1@782.61,596.57
  Bottom Layer w100: J5.2@4147.5,288.7 4371.68,288.7 TP25.1@4371.89,288.91
  other v3: 1604.86,1275.57 974.91,1399.99 1588.97,1454.95 1291.33,1459.84 1315.83,1499 4155.72,1507.22 4206.9,1507.22 1239.32,1510.87 4155.72,1550.53 4206.9,1550.53 4155.72,1593.83 4206.9,1593.83 4155.72,1637.14 4206.9,1637.14 1521.78,1645.19 4155.72,1680.45 4206.9,1680.45 4155.72,1723.76 4206.9,1723.76 110.99,1883.17 230.52,2200.49 166.13,2280.94 331.06,2282.41 1990.01,2303.33 1679.19,2320.24 449.92,2337.53 1892.48,2340.6 73.8,2344.2 103.92,2442.58 1955.65,2555.47 98.86,2574.08 85.9,2634.57
  other v5: 1642.59,983.19
  other v7: 1160.61,688.57 153.24,1280.43
  other v8: 150.14,354.86 193.45,354.86 315.39,1081.98 295.7,1106.58 335.07,1106.58 315.39,1131.19
  other v9: 1056.77,331.16
GUI_STATUS: D2.2 U1.30 | length 561.8
  Top Layer w12.83: v1(348.81,2018.99) 351.02,2018.99 370.87,2038.85 D2.2@372.59,2038.85 ; v1(617.39,1826.47) 641.61,1802.24 677.13,1802.24 U1.30@677.64,1801.73
  Mid-Layer 2 w12.83: v1(348.81,2018.99) 348.81,1857.18 399.07,1806.92 496.14,1806.92 515.68,1826.47 v1(617.39,1826.47)
HFXIN: C7.2 U1.45 Y1.3 | length 259.5
  Top Layer w6: U1.45@990.64,1685.59 990.64,1538.51 C7.2@1015.46,1513.68 1032.38,1496.76 1085.21,1496.76 Y1.3@1085.61,1497.16
HFXOUT: C6.2 U1.46 Y1.1 | length 231.4
  Top Layer w6: U1.46@1010.32,1685.59 1013.23,1682.69 1013.23,1652.7 1030.36,1635.57 1041.79,1635.57 1069.46,1607.9 1107.24,1607.9 1132.66,1582.48 1136.95,1582.48 1159.27,1560.15 Y1.1@1172.22,1560.15
ILIM: J9.1 J9.3 J9.5 J9.7 J9.9 J9.11 J9.13 U3.14 | length 2051.1
  Top Layer w12.83: U3.14@4267.92,1524.94 4314.31,1524.94 4321.82,1517.42 4321.82,1464.85 4313.73,1456.76 v1@4313.73,1452.74
  Top Layer w29.53: J9.1@3304.36,785.4 3308.12,781.65 J9.9@3308.12,386.13 J9.11@3308.12,286.13 J9.13@3308.12,186.13
  Mid-Layer 2 w29.53: J9.1@3308.12,786.13 3420.92,898.93 v1(3420.92,966.72) ; v1@3418.18,970.72 3686.92,1239.46 4101.08,1239.46 v1(4315.83,1454.21)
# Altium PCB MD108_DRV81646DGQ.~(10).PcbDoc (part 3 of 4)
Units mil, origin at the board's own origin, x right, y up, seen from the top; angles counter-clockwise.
Board outline 6002 x 2931.52 mil, 4 copper layers (Top Layer, Mid-Layer 1, Mid-Layer 2, Bottom Layer), stack 92.712 mil thick; 255 components, 141 nets, 784 pads, 239 vias.
Unrouted connection lines stored in the file: 111.

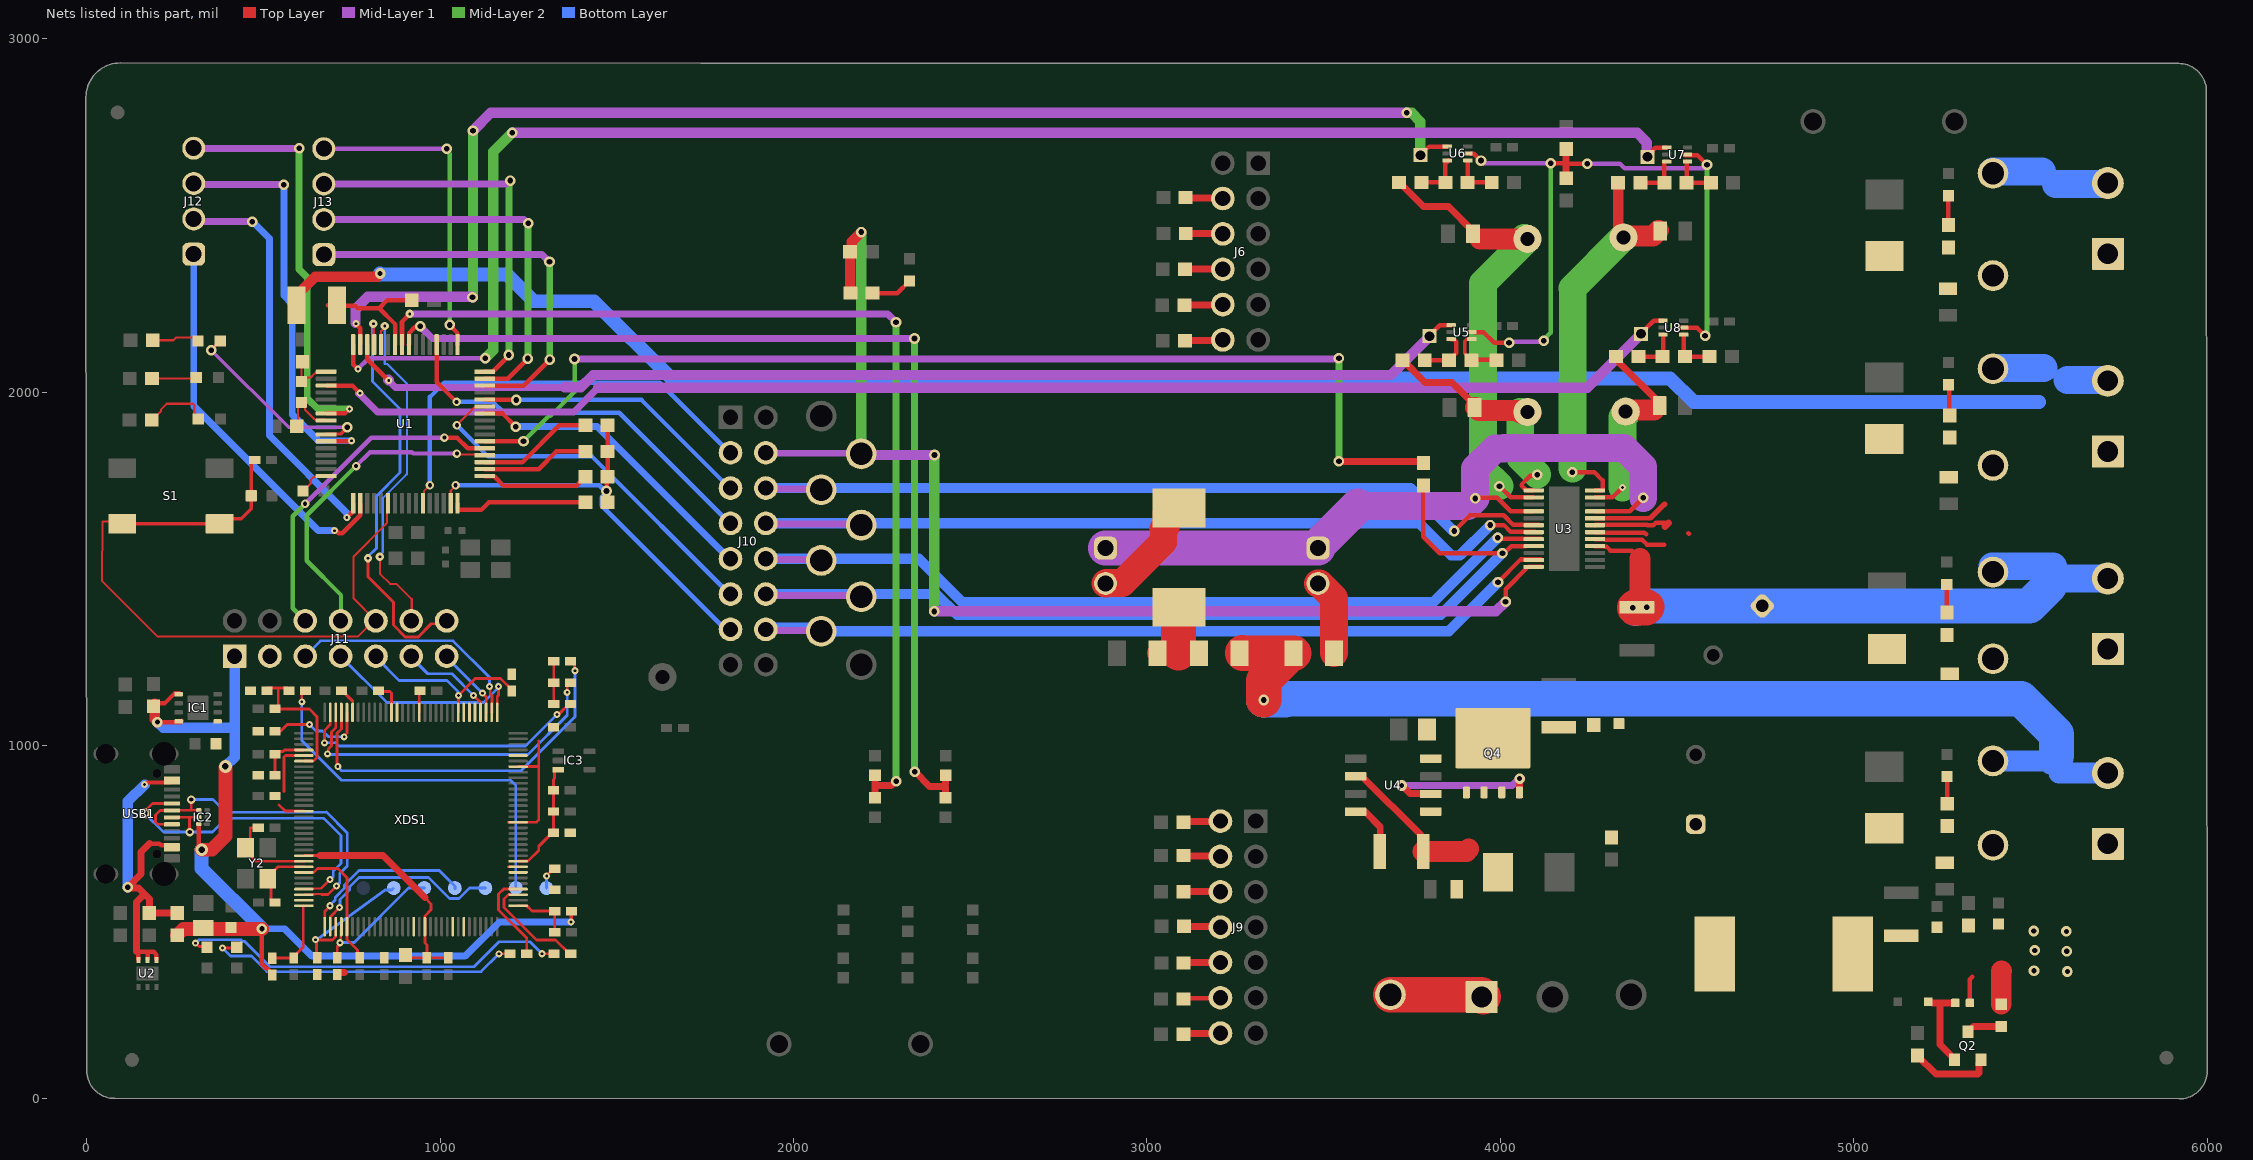
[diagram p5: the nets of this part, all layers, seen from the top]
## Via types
v1: diameter 30, hole 16, Top Layer to Bottom Layer, tented both sides, 89 vias
v2: diameter 20, hole 8, Top Layer to Bottom Layer, tented both sides, 47 vias
v3: diameter 19.68, hole 7.87, Top Layer to Bottom Layer, tented both sides, 35 vias
v4: diameter 24, hole 12, Top Layer to Bottom Layer, tented both sides, 14 vias
v5: diameter 24, hole 7.87, Top Layer to Bottom Layer, tented both sides, 11 vias
v6: diameter 30, hole 15, Top Layer to Bottom Layer, tented both sides, 10 vias
v7: diameter 28, hole 14, Top Layer to Bottom Layer, tented both sides, 9 vias
v8: diameter 19.68, hole 7.87, Top Layer to Bottom Layer, 6 vias
v9: diameter 24, hole 8, Top Layer to Bottom Layer, tented both sides, 5 vias
v10: diameter 30, hole 14, Top Layer to Bottom Layer, tented both sides, 4 vias
v11: diameter 24, hole 11.81, Top Layer to Bottom Layer, tented both sides, 4 vias
v12: diameter 36, hole 18.29, Top Layer to Bottom Layer, tented both sides, 2 vias
v13: diameter 30, hole 15.75, Top Layer to Bottom Layer, tented both sides, 2 vias
v14: diameter 34, hole 16, Top Layer to Bottom Layer, tented both sides, 1 vias

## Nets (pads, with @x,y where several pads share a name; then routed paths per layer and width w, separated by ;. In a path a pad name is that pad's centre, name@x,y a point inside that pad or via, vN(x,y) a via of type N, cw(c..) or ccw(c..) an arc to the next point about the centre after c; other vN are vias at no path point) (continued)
INA_REF: R63.1 R64.2 U5.5 U6.5 U7.5 U8.5 | length 2130.4
  Top Layer w12.83: U6.5@3914.83,2674.7 3924.4,2674.7 3943.95,2655.15 v1(3945.51,2655.15) ; U5.5@3926.21,2169.82 3952.56,2169.82 3982.44,2139.93 v1(4024.76,2139.93) ; v1(4143.21,2648.02) 4182.5,2648.02 4183,2648.51 ; 4183,2647.4 4183.98,2647.4 ; 4187.49,2646.52 v1(4245.67,2646.52) ; U8.5@4511.29,2181.95 4511.73,2181.51 4557.18,2181.51 4579.12,2159.56 v1(4579.43,2159.56) ; U7.5@4521.24,2672.89 4523.26,2670.86 4557.58,2670.86 v1(4584.9,2643.54)
  Top Layer w19.68: R64.2@4186.49,2605.18 4186.49,2647.52 ; 4186.49,2648.51 R63.1@4186.49,2687.33
  Mid-Layer 1 w12.83: v1(3945.51,2655.15) 3945.71,2655.15 3952.83,2648.02 v1(4143.21,2648.02) ; v1(4024.76,2139.93) 4027.37,2142.53 4120.21,2142.53 v1(4122.81,2145.14) ; v1(4245.67,2646.52) 4338.64,2646.52 4351.51,2633.66 4575.02,2633.66 v1(4584.9,2643.54)
  Mid-Layer 2 w12.83: v1(4122.81,2145.14) 4122.81,2148.16 4143.21,2168.55 v1(4143.21,2648.02) ; v1(4579.43,2159.56) 4584.9,2165.03 v1(4584.9,2643.54)
IRSTN: R15.1 TP6.1 | length 1093.4
  Top Layer w8: v2(608.61,1123.57) 608.61,1147.57 R15.1@616.61,1155.57
  Bottom Layer w8: v2(608.61,1123.57) 608.61,1014.28 721.33,901.57 1199.61,901.57 1214.28,886.9 TP6.1@1214.28,596.57
ITCK: R26.2 TP3.1 XDS1.100 | length 407.9
  Top Layer w8: R26.2@709.08,399.58 709.08,430.64 v2@716.85,438.41 ; v2(716.97,441.78) 718.95,443.76 718.95,475.91 720.37,477.33 XDS1.100@720.37,506.23
  Bottom Layer w8: v2@719.28,442.86 757.22,442.86 910.93,596.57 TP3.1@955.28,596.57 TP3.1@955.61,596.57
ITDI: TP5.1 XDS1.98 | length 566.9
  Top Layer w8: XDS1.98@689.27,487.42 689.27,515 715.61,541.35 v2(715.61,541.57)
  Bottom Layer w8: v2(715.61,541.57) 717.15,543.1 717.15,564.24 743.73,590.83 743.73,599.67 770.32,626.25 846.5,626.25 967.58,626.25 1026.95,566.88 1053.91,566.88 1083.6,596.57 TP5.1@1127.95,596.57
ITDO: TP4.1 XDS1.97 | length 473.3
  Top Layer w8: XDS1.97@673.52,510.98 673.52,530.55 688.61,545.64 v2(688.61,546.57)
  Bottom Layer w8: v2(688.61,546.57) 688.61,548.62 703.15,563.15 703.15,570.04 729.73,596.63 729.73,605.46 770.83,646.57 997.61,646.57 1042.61,601.57 TP4.1@1042.61,594.57
ITMS: R25.2 TP2.1 XDS1.99 | length 427.7
  Top Layer w8: v2(647.64,450.58) 648.37,449.86 695.04,449.86 704.92,459.74 XDS1.99@704.92,510.43 ; v2@649.94,445.98 649.94,402.24 R25.2@652.61,399.57 ; R25.2@652.25,399.03 R25.2@652.25,399.57
  Bottom Layer w8: v2@647.37,448.68 648.45,449.46 845.38,591.33 863.38,591.33 TP2.1@867.1,595.05
MCU_nFAULT: J10.3 U1.43 | length 1252.6
  Top Layer w6: U1.43@951.27,1685.59 954.17,1688.5 954.17,1719.64 v4(971.22,1736.69)
  Bottom Layer w12.83: v4(971.22,1736.69) 971.22,1986.29 1011.47,2026.54 1621.09,2026.54 1816.67,1830.95 J10.3@1816.67,1830.5
MCU_nSCS/IN3: J10.9 U1.58 | length 868.5
  Top Layer w12.83: U1.58@1126.46,1939.53 1176.69,1939.53 v13(1213.86,1902.36)
  Bottom Layer w19.68: v13(1213.86,1902.36) 1444.04,1902.36 1816.09,1530.3 J10.9@1825.45,1530.3
MCU_SCLK/IN2: J10.7 U1.4 | length 1119.7
  Top Layer w12.83: U1.4@990.21,2158.38 990.21,2028.48 v4(1046.58,1972.11)
  Bottom Layer w12.83: v4(1046.58,1972.11) 1148.99,1972.11 1180,1941.1 1506.53,1941.1 1814.92,1632.71 J10.7@1816.09,1632.71
MCU_SDI/IN1: J10.5 U1.60 | length 793.9
  Top Layer w12.83: U1.60@1126.46,1978.9 1126.97,1978.39 1215.21,1978.39 v13(1215.85,1977.75)
  Bottom Layer w12.83: v13(1215.85,1977.75) 1569.88,1977.75 1814.85,1732.78 J10.5@1818.43,1732.78
MCU_SDO/IN4: J10.11 U1.59 | length 1073.6
  Top Layer w6: v4(1047.63,1906.06) 1047.63,1907.71 1096.22,1956.31 1123.56,1956.31 U1.59@1126.46,1959.21 U1.59@1129.37,1962.12
  Bottom Layer w12.83: v4(1047.63,1906.06) 1135.74,1817.95 1429.68,1817.95 J10.11@1817.97,1429.65
MCU_STATUS: D1.2 U1.26 | length 579.9
  Top Layer w9.84: v1(352.71,2118.82) 352.71,2119.94 375.83,2143.06 D1.2@375.83,2145.42 ; U1.26@677.64,1880.47 678.63,1881.46 719.02,1881.46 v1(737.65,1900.09)
  Mid-Layer 1 w9.84: v1(352.71,2118.82) 571.44,1900.09 v1(737.65,1900.09)
NetC3_2: C3.2 U1.32 | length 88.7
  Top Layer w6: C3.2@612.52,1720 633.9,1741.38 633.9,1751.67 641.68,1759.46 674.74,1759.46 U1.32@677.64,1762.36
NetC8_1: C8.1 R14.1 R15.2 XDS1.70 | length 395.5
  Top Layer w8: R14.1@509,1162.79 509.5,1162.28 569.97,1162.28 R15.2@570.48,1161.77 ; 542.08,1160.69 542.08,1103.1 630.14,1103.1 652.02,1081.22 652.02,965.9 642.05,955.92 XDS1.70@614.46,955.92
NetC12_1: C12.1 R22.1 XDS1.68 | length 131.9
  Top Layer w8: R22.1@532.62,916.14 C12.1@532.62,975.59 ; C12.1@544.27,983.31 544.37,983.4 554.99,983.4 559.3,987.71 XDS1.68@614.92,987.71
NetC16_1: C16.1 XDS1.88 Y2.3 | length 274.4
  Top Layer w8: C16.1@485.37,767.24 462.72,767.24 462.72,729.71 445.17,712.16 445.17,706.25 464.79,686.63 472.96,678.46 472.96,678.09 478.6,672.46 XDS1.88@614.46,672.46
NetC17_1: C17.1 C18.1 IC3.3 R28.1 XDS1.9 | length 328.6
  Top Layer w8: XDS1.9@1221.22,672.75 1221.28,672.82 1248.86,672.82 1279.11,703.07 1279.11,715.02 1317.17,753.08 R28.1@1321.11,753.08 C18.1@1321.11,813.04 C17.1@1321.11,873 1321.11,904.22 1323.56,906.67 1323.56,928.1 1327.43,931.98 IC3.3@1334.32,931.98
NetC23_1: C23.1 XDS1.89 Y2.1 | length 197.2
  Top Layer w8: C23.1@533.04,555.64 529.1,555.64 521.29,563.45 521.29,614.48 Y2.1@512.19,623.58 512.19,627.51 541.38,656.71 XDS1.89@614.46,656.71
NetC24_1: C24.1 R24.2 XDS1.96 | length 217.5
  Top Layer w8: R24.2@527.61,400.57 529.15,399.03 C24.1@585.83,399.03 585.83,402.97 612.61,429.75 XDS1.96@612.61,546.57
NetC27_1: C27.1 C28.1 C29.1 XDS1.87 XDS1.115 | length 699
  Top Layer w8: XDS1.87@614.92,688.5 660.61,688.57 ; C27.1@902.34,399.58 C28.1@962.68,399.58 ; 956.98,569.57 956.98,569.48 974.61,551.85 974.61,535.28 957.05,517.72 957.05,487.48 XDS1.115@956.98,487.42 956.98,440.85 962.68,435.15 C28.1@962.68,399.58 ; C29.1@1023.03,399.58 C28.1@962.68,399.58
  Top Layer w20: 660.61,688.57 837.98,688.57 956.98,569.57
NetC51_1: C51.1 U4.4 | length 156.8
  Top Layer w19.68: U4.4@3590.53,812.81 3591.81,811.53 3618.41,811.53 3660.25,769.69 C51.1@3660.25,746.45 ; C51.1@3659.52,700.46 C51.1@3659.52,746.45
NetD1_1: D1.1 R1.2 | length 134.9
  Top Layer w6: R1.2@186.79,2146.65 244.95,2146.65 252.5,2154.19 305.68,2154.19 D1.1@314.82,2145.05
NetD2_1: D2.1 R2.2 | length 126.2
  Top Layer w6: R2.2@184.73,2038.49 307.51,2038.49 D2.1@309.93,2040.9
NetD3_1: D3.1 R3.2 | length 188.3
  Top Layer w6: R3.2@184.03,1921.12 185.02,1921.12 210.05,1946.15 210.53,1946.15 210.53,1951.15 226.37,1966.99 300.9,1966.99 304.42,1963.48 304.42,1934.65 D3.1@315.53,1923.54
NetD4_1: D4.1 R31.1 | length 1134.6
  Top Layer w8: v2(307.61,440.57) 308.34,440.57 317.84,431.06 D4.1@344.61,431.06 ; v2(1288.36,410.78) R31.1@1322.45,410.78
  Bottom Layer w8: v2(307.61,440.57) 308.57,440.57 318.3,450.3 435.82,450.3 440.24,445.88 447.27,445.88 519.1,374.04 1096.27,374.04 1166.8,444.57 1254.57,444.57 v2(1288.36,410.78)
NetD5_1: D5.1 R27.1 | length 902.9
  Top Layer w8: v2(384.61,426.57) 422.07,426.57 D5.1@424.61,429.11 ; v2(1166.61,410.57) 1166.72,410.67 1197.77,410.67 R27.1@1197.88,410.78
  Bottom Layer w8: v2(384.61,426.57) 406.61,404.57 466.11,404.57 510.64,360.04 1116.09,360.04 v2(1166.61,410.57)
NetD6_1: D6.1 R34.2 | length 137
  Top Layer w12.91: R34.2@2211.29,2267.86 R34.2@2218.69,2275.26 ; R34.2@2217,2276.95 2220.15,2280.1 R34.2@2223.77,2280.1 2293.91,2280.1 D6.1@2328.08,2314.26
NetD7_1: D7.1 J7.2 | length 333.3
  Top Layer w78.74: J7.2@2884.15,1457.57 J7.2@2883.02,1458.7 2884.15,1459.83 2930.01,1459.83 3047.43,1577.25 3047.43,1613.32 3054.69,1620.57 3054.69,1656.64 3063.36,1665.31 D7.1@3086.86,1665.31
NetD7_2: D7.2 R50.2 R51.1 | length 244
  Top Layer w59.06: R50.2@3030,1261.31 3089.49,1261.31 R51.1@3143.63,1261.31
  Top Layer w98.43: 3089.49,1261.31 3089.49,1390.46 D7.2@3090.32,1391.28
NetD13_1: D13.1 R77.2 | length 81.5
  Top Layer w12.83: D13.1@5268.29,2555.76 5268.12,2555.6 5268.12,2476.62 R77.2@5269.76,2474.98
NetD14_1: D14.1 R78.2 | length 87
  Top Layer w12.83: D14.1@5268.47,2020.86 5270.05,2019.28 5270.05,1935.1 R78.2@5269.65,1934.71
NetD15_1: D15.1 R79.2 | length 77.9
  Top Layer w12.83: R79.2@5262.61,1378.55 5263.71,1379.65 5263.71,1455.66 D15.1@5263.45,1455.92
NetD16_1: D16.1 R80.2 | length 79.7
  Top Layer w12.83: D16.1@5264.42,912.02 R80.2@5264.42,835.25 5264.42,833.39 R80.2@5265.17,832.63
NetD17_1: D17.1 Q2.1 R81.1 | length 258.1
  Top Layer w19.68: D17.1@5210.92,274.75 5212.89,272.78 5221.76,272.78 5222.94,271.59 5244.51,271.59 5286.53,271.59 5287.2,272.25 5287.5,271.95 R81.1@5287.5,271.59 ; 5240.84,271.59 5244.51,267.92 5244.51,153.75 5285.61,112.65 Q2.1@5285.61,110.68
NetD18_1: D18.1 Q2.3 | length 107.4
  Top Layer w19.68: Q2.3@5323.01,189.42 5323.01,191.39 5328.92,197.3 5330.89,197.3 5338.46,204.87 5417.18,204.87 D18.1@5421.22,200.84
NetJ6_4: J6.4 R45.2 | length 110.9
  Top Layer w19.68: R45.2@3109.59,2550.3 3110.85,2549.04 3219.81,2549.04 J6.4@3219.92,2548.93
NetJ6_6: J6.6 R46.2 | length 104.4
  Top Layer w19.68: R46.2@3109.89,2449.01 3110.5,2448.39 3213.85,2448.39 J6.6@3213.97,2448.27
NetJ6_8: J6.8 R47.2 | length 113.1
  Top Layer w19.68: R47.2@3107.76,2347.62 3107.83,2347.7 3214.51,2347.7 J6.8@3219,2352.2
NetJ6_10: J6.10 R48.2 | length 110.3
  Top Layer w19.68: R48.2@3106.38,2246.05 3107.25,2246.91 3213,2246.91 J6.10@3215.34,2249.26
NetJ6_12: J6.12 R49.2 | length 104.8
  Top Layer w19.68: R49.2@3107.76,2145.4 3108.94,2146.59 3209.12,2146.59 J6.12@3211.23,2144.49
NetJ8_2: J8.2 R52.1 | length 218.1
  Top Layer w78.74: J8.2@3484.34,1458.63 3488.06,1458.63 3529.28,1417.41 R52.1@3529.28,1261.31
NetJ9_2: J9.2 R53.2 | length 109.2
  Top Layer w19.68: R53.2@3103.19,782.73 3104.88,784.43 3210.03,784.43 J9.2@3211.21,783.25
NetJ9_4: J9.4 R54.2 | length 111.2
  Top Layer w19.68: R54.2@3103.19,688.45 3104.35,687.29 3210.96,687.29 J9.4@3213.07,685.18
NetJ9_6: J9.6 R55.2 | length 108.8
  Top Layer w19.68: R55.2@3103.19,586.38 3103.31,586.25 3211.49,586.25 J9.6@3211.8,586.56
NetJ9_8: J9.8 R56.2 | length 110.6
  Top Layer w19.68: R56.2@3104.67,488.58 3105.89,487.35 3205.93,487.35 J9.8@3212.14,481.14
NetJ9_10: J9.10 R57.2 | length 105.9
  Top Layer w19.68: R57.2@3103.74,384.93 3104.33,385.53 3207.62,385.53 J9.10@3208.88,386.79
NetJ9_12: J9.12 R58.2 | length 101.4
  Top Layer w12.83: R58.2@3103.19,283.06 3104.72,284.6 3203.36,284.6 J9.12@3203.77,285.01
NetJ9_14: J9.14 R59.2 | length 107.7
  Top Layer w19.68: R59.2@3103.19,183.06 3104.72,184.59 3208.87,184.59 J9.14@3209.81,185.54
NetQ2_2: Q2.2 R82.2 | length 246.6
  Top Layer w12.83: R82.2@5175.2,117.47 R82.2@5180.71,122.99
  Top Layer w19.68: R82.2@5180.71,122.99 5180.71,122 5232.81,69.91 5351.15,69.91 5354.51,73.27 5354.51,102.81 5362.49,110.8 Q2.2@5362.68,110.8
NetQ4_4: Q4.4 U4.6 | length 479.2
  Top Layer w19.68: v10(3721.13,886.72) 3722.3,886.72 3744.23,864.78 3801.16,864.78 U4.6@3803.12,862.81 ; Q4.4@4054.58,860.56 v10(4054.58,906.33)
  Mid-Layer 1 w19.68: v10(3721.13,886.72) 4033.8,886.72 4053.41,906.33 v10(4054.58,906.33)
NetR16_2: R16.2 XDS1.59 | length 85.2
  Top Layer w8: R16.2@713.34,1160.69 717.28,1160.69 752.65,1125.32 XDS1.59@752.65,1094.08
NetR18_1: R18.1 XDS1.61 | length 1039.8
  Top Layer w8: v2(710.61,940.57) 708.61,942.57 708.61,1034.77 720.7,1046.85 XDS1.61@720.7,1070.16 ; R18.1@1368.82,1238.25 1372.75,1238.25 1380.56,1230.44 1380.56,1212.62 v2(1381.61,1211.57)
  Bottom Layer w8: v2(710.61,940.57) 710.61,939.25 721.3,928.57 1228.61,928.57 1381.61,1081.57 v2(1381.61,1211.57)
NetR19_1: R19.1 XDS1.62 | length 925
  Top Layer w8: v2(681.61,976.57) 683.31,978.27 683.31,989.98 692.61,999.28 692.61,1038.57 704.95,1050.91 XDS1.62@704.95,1070.16 ; v2(1359.61,1150.57) 1359.61,1170.1 1367.43,1177.91 R19.1@1368.82,1177.91
  Bottom Layer w8: v2(681.61,976.57) 683.61,974.57 1248.61,974.57 1359.61,1085.57 v2(1359.61,1150.57)
NetR20_1: R20.1 XDS1.63 | length 818.7
  Top Layer w8: v2(672.61,1007.57) 672.61,1042.57 689.27,1059.22 XDS1.63@689.27,1070.16 ; v2(1330.61,1087.57) 1332.91,1089.86 1337.17,1089.86 1364.88,1117.57 R20.1@1368.82,1117.57
  Bottom Layer w8: v2(672.61,1007.57) 705.2,1007.57 714.2,998.57 1241.61,998.57 v2(1330.61,1087.57)
NetR21_1: R21.1 XDS1.60 | length 279.3
  Top Layer w8: R21.1@544.27,1040.25 548.21,1040.25 567.61,1059.65 630.53,1059.65 v2(630.61,1059.57) ; v2(728.61,1024.57) 728.61,1027.81 736.51,1035.71 XDS1.60@736.51,1093.72
  Bottom Layer w8: v2(630.61,1059.57) 649.26,1040.92 667.55,1040.92 683.9,1024.57 v2(728.61,1024.57)
NetR27_2: R27.2 XDS1.4 | length 263.2
  Top Layer w8: XDS1.4@1221.15,593.95 1180,593.95 1165.61,579.57 1165.61,534.57 1245.12,455.06 R27.2@1245.12,410.78
NetR31_2: R31.2 XDS1.3 | length 288.9
  Top Layer w8: XDS1.3@1197.2,577.97 1193.18,577.97 1180.61,565.4 1180.61,541.57 1272.48,449.7 1326.83,449.7 1365.75,410.78 R31.2@1369.69,410.78
nFAULT: J10.4 R33.1 R34.1 TP11.1 U3.12 | length 3531.7
  Top Layer w12.83: v1(4014.92,1406.95) 4014.92,1442.25 4079.05,1506.38 U3.12@4116.63,1506.38
  Top Layer w29.53: R34.1@2157.63,2281 2160.11,2283.47 2160.11,2396.35 R33.1@2159.43,2397.03 ; R33.1@2159.43,2400.17 2163.57,2400.17 2164.35,2400.96 2164.35,2425.06 2192.04,2452.75 v1(2192.04,2452.88)
  Mid-Layer 1 w19.68: J10.4@1918.99,1828.64 1920.71,1826.92 TP11.1@2189.28,1826.92
  Mid-Layer 1 w29.53: TP11.1@2189.28,1827.85 2195.19,1821.94 v1(2399.09,1821.94) ; v1(2398.29,1379.36) 3987.33,1379.36 v1(4014.92,1406.95)
  Mid-Layer 2 w29.53: TP11.1@2191.45,1825.2 2191.45,2378.82 2192.04,2379.42 v1(2192.04,2452.88) ; v1(2398.29,1379.36) 2398.29,1821.13 v1(2399.09,1821.94)
nSCS/IN3: J10.10 TP12.1 U3.8 | length 2463.8
  Top Layer w12.83: v1(3992.78,1588.16) 3996.06,1584.87 4008.2,1584.87 4008.25,1584.82 U3.8@4115.62,1584.82
  Mid-Layer 1 w19.68: J10.10@1918.99,1528.64 1921.52,1526.11 2053.06,1526.11 TP12.1@2059.75,1532.79
  Bottom Layer w29.53: J10.10@1926.19,1532.57 1930.12,1528.64 2354.43,1528.64 2477.68,1405.39 3810.01,1405.39 v1(3992.78,1588.16)
OUT1: C53.2 D9.2 J1.1 R77.1 TP17.1 U3.20 | length 227.5
  Top Layer w12.83: U3.20@4267.92,1643.05 4426.26,1643.05 ; D9.2@5077.56,2394.98 D9.2@5087.03,2385.51
  Top Layer w15.75: 4424.96,1644.14 4465.04,1682.96
OUT2: C54.2 D10.2 J2.1 R78.1 TP18.1 U3.19 | length 225.2
  Top Layer w12.83: U3.19@4267.92,1623.36 4268.77,1624.21 4416.19,1624.21 4416.56,1623.85 4433.17,1623.85 cw(c4438.49,1612.17) 4434.06,1624.21 4439.65,1629.8 4476.22,1629.8
  Top Layer w19.68: 4466.34,1619.92 4476.22,1629.8
OUT3: C55.2 D11.2 J3.1 R79.1 TP19.1 U3.18 | length 150.3
  Top Layer w12.83: U3.18@4267.92,1603.68 4268.43,1603.16 4293.39,1603.16 4294.24,1602.31 4407.97,1602.31 4412.66,1597.63 ; 4531.8,1600.72 4533.95,1598.57
OUT4: C56.2 D12.2 J4.1 R80.1 TP22.1 U3.17 | length 202
  Top Layer w12.83: U3.17@4267.92,1583.99 4268.43,1583.48 4293.39,1583.48 4294.24,1582.63 4401.02,1582.63 4415,1568.65 4463.57,1568.65
PA0: J12.2 U1.33 | length 1165.2
  Top Layer w12.83: v2(735.95,1645.19) 736.61,1645.19 754.42,1662.99 U1.33@754.42,1685.59
  Mid-Layer 1 w19.68: J12.2@305.41,2490.25 312.36,2483.3 467.92,2483.3 v1(468.74,2482.47)
  Bottom Layer w19.68: J12.2@322.69,2485.06 322.69,2484.4 J12.2@323.79,2483.3 ; v1(468.74,2482.47) 517.07,2434.14 517.07,1876.73 735.89,1657.91 v2(735.95,1645.19) v2(735.95,1645.19)
PA1: J12.1 U1.34 | length 1107.7
  Top Layer w12.83: v2(701.29,1607.9) 702.66,1606.53 707.46,1606.53 712.91,1601.08 723.55,1601.08 773.59,1651.12 773.59,1685.08 U1.34@774.1,1685.59
  Bottom Layer w19.68: J12.1@297.63,2390.86 302.88,2385.62 302.88,1960.21 655.19,1607.9 v2(701.29,1607.9)
PB10: J13.1 U1.62 | length 1141.5
  Top Layer w12.83: U1.62@1126.46,2018.27 1236.54,2018.27 v1(1310.32,2092.04)
  Mid-Layer 1 w19.68: J13.1@668.99,2391.4 671.63,2388.76 1288.53,2388.76 1308.44,2368.85 v1(1309.61,2368.85)
  Mid-Layer 2 w19.68: v1(1309.61,2368.85) 1310.32,2368.14 v1(1310.32,2092.04)
PB11: J13.2 U1.63 | length 1118.7
  Top Layer w12.83: U1.63@1126.46,2037.95 1191.26,2037.95 v1(1248.18,2094.87)
  Mid-Layer 1 w19.68: J13.2@666.13,2483 671.89,2488.76 1236.98,2488.76 1248.11,2477.63 v1(1249.28,2477.63)
  Mid-Layer 2 w19.68: v1(1248.18,2094.87) 1248.18,2476.53 v1(1249.28,2477.63)
PB12: J13.3 U1.64 | length 1118.7
  Top Layer w12.83: U1.64@1126.46,2057.64 1149.06,2057.64 1194.63,2103.21 v1(1194.63,2105.11)
  Mid-Layer 1 w19.68: J13.3@669.6,2590.54 671.38,2588.76 1187.29,2588.76 1197.13,2598.61 v1(1198.3,2598.61)
  Mid-Layer 2 w12.83: v1@1193.17,2592.01 v1@1194.63,2590.54
  Mid-Layer 2 w19.68: v1@1193.17,2592.01 1193.17,2593.47 v1(1198.3,2598.61) ; v1(1194.63,2105.11) v1@1194.63,2590.54
PB13: J13.4 U1.1 | length 916.7
  Top Layer w12.83: v1(1027.23,2190.04) 1027.23,2189.04 1049.18,2167.09 1049.18,2134.92 U1.1@1049.69,2134.41
  Mid-Layer 1 w12.83: J13.4@668.99,2687.52 669.94,2688.47 1018.19,2688.47 v1(1018.48,2688.19)
  Mid-Layer 2 w12.83: v1(1018.48,2688.19) 1018.48,2683.54 1027.23,2674.79 v1(1027.23,2190.04)
PB24: J12.4 U1.23 | length 1216.3
  Top Layer w12.83: U1.23@677.64,1939.53 730.89,1939.53 v2(743.27,1951.94)
  Mid-Layer 1 w19.68: J12.4@304.95,2688.5 306.39,2689.94 601,2689.94 v1(601.22,2689.72)
  Mid-Layer 2 w19.68: v1(601.22,2689.72) 601.22,2347.55 624.12,2324.65 624.12,1982.48 654.66,1951.94 v2(743.27,1951.94)
PB25: J12.3 U1.27 | length 1188
  Top Layer w12.83: U1.27@677.64,1860.79 678.16,1861.3 748.63,1861.3 v2(749.67,1862.33)
  Mid-Layer 1 w19.68: J12.3@303.68,2592.22 308.04,2587.86 556.93,2587.86 v1(557.76,2587.04)
  Bottom Layer w19.68: v1(557.76,2587.04) 557.76,2273.76 581.65,2249.88 581.65,1936.6 655.92,1862.33 v2(749.67,1862.33)
PI_IN: C41.2 C42.2 C43.1 C44.2 C45.1 C52.1 L1.1 Q4.5 Q4.6 Q4.7 Q4.8 Q4.9@3979.19,1020.79 U4.8
PVDD_ADC: R4.1 R5.2 U1.10 | length 371.8
  Top Layer w12.83: R4.1@682.45,2246.08 705.82,2246.08 708.04,2243.86 760.68,2243.86 766.97,2237.57 827.55,2237.57 ; U1.10@872.53,2134.41 872.53,2192.6 827.55,2237.57 ; R5.2@919.69,2259.83 849.81,2259.83 827.55,2237.57
REF_TARGET_VCC: XDS1.120
REV_ID1: R35.2 R36.1 U1.9 | length 2898.6
  Top Layer w12.83: U1.9@892.21,2134.41 892.21,2199 v5(914.42,2221.22)
  Top Layer w19.68: R36.1@2228.71,860.43 2230.96,862.68 2230.96,886.19 ; R35.2@2231.11,911.91 2230.96,911.76 2230.96,886.19 ; v1(2291.04,898.69) 2288.25,898.69 2275.74,886.19 2230.96,886.19
  Mid-Layer 1 w19.68: v5(914.42,2221.22) 2266.71,2221.22 v1(2290.08,2197.85)
  Mid-Layer 2 w19.68: v1(2290.08,2197.85) 2290.08,899.65 v1(2291.04,898.69)
REV_ID2: R37.2 R38.1 U1.8 | length 2869.7
  Top Layer w12.83: U1.8@911.9,2134.41 912.41,2134.92 912.41,2167.09 928.37,2183.05 940.2,2183.05 v1(943.48,2186.33)
  Top Layer w19.68: v1(2343.44,925.95) 2384.88,884.51 2430.35,884.51 2430.35,854.87 R38.1@2429.82,854.34 ; 2430.35,892.11 2430.35,915.6 R37.2@2430.64,915.89
  Mid-Layer 1 w19.68: v1(943.48,2186.33) 978.14,2151.68 v1(2342.36,2151.68)
  Mid-Layer 2 w19.68: v1(2342.36,2151.68) 2342.36,927.03 v1(2343.44,925.95)
RS700_HW(GND): R9.1 U1.51 | length 327.7
  Top Layer w12.83: U1.51@1126.46,1801.73 1233.05,1801.73 1337.39,1906.07 R9.1@1410.99,1906.07
RS700_SPI(GND): R10.1 U1.50 | length 305.2
  Top Layer w12.83: U1.50@1126.46,1782.05 1278.92,1782.05 1328.9,1832.03 R10.1@1410.99,1832.03
RS1500_HW(GND): R11.1 U1.49 | length 307.6
  Top Layer w12.83: U1.49@1126.46,1762.36 1126.97,1761.85 1152.91,1761.85 1180.4,1734.36 1384.79,1734.36 1397.72,1747.3 1397.72,1748.28 1410,1760.56 R11.1@1410.99,1760.56
RS1500_SPI(GND): R12.1 U1.48 | length 388.4
  Top Layer w12.83: U1.48@1049.69,1685.59 1049.69,1667.49 1050.2,1666.98 1117,1666.98 1138.3,1688.28 R12.1@1410.99,1688.28
RSLEW/CNTL: J10.14 TP9.1 U3.11 | length 2435.3
  Top Layer w12.83: v1(3993.46,1462.41) 4057.34,1526.3 U3.11@4115.12,1526.3
  Mid-Layer 1 w19.68: J10.14@1918.99,1328.64 1921.75,1325.88 2050.39,1325.88 TP9.1@2054.03,1329.52
  Bottom Layer w29.53: J10.14@1910.08,1324.23 1919.62,1333.76 2059.56,1333.76 2070.2,1323.12 3854.17,1323.12 v1(3993.46,1462.41)
RSLEW/CNTL_GND/HiZ/VDD: J10.13 R9.2 R10.2 R11.2 R12.2 U1.47 | length 1261.7
  Top Layer w6: U1.47@1030.01,1685.59 1030.01,1721.23 1043.65,1734.88 v4(1043.65,1736.69) ; R9.2@1473.98,1898.6 R9.2@1473.98,1906.07
  Top Layer w12.83: R9.2@1473.98,1898.6 R10.2@1473.98,1832.03 R11.2@1473.98,1760.56 1470.97,1757.55 1470.97,1699.96 R12.2@1475.52,1695.4
  Bottom Layer w12.83: v4(1043.65,1736.69) 1449.87,1736.69 1466.32,1720.24 v1(1470.97,1720.24) 1470.97,1715.59 1457.42,1702.05 1457.42,1678.07 1810.99,1324.5 J10.13@1820.21,1324.5
RST: C2.1 J11.10 R8.1 S1.1 S1.2 U1.38 | length 1998.7
  Top Layer w5.91: 44.28,1634.02 43,1466.48 201.27,1308.21 766.91,1308.21 811.42,1352.72 J11.10@818.44,1352.72 ; J11.10@818.44,1352.72 755.01,1416.17 755.01,1534.35 845.2,1624.53 845.2,1625.3 850.01,1630.12 850.01,1673.95 U1.38@852.84,1676.78
  Top Layer w6: 44.28,1634.02 S1.2@99.86,1634.02
  Top Layer w9.84: S1.2@100.52,1627.65 S1.1@372.49,1627.65 ; S1.1@376.12,1627.65 389.78,1641.32 437.28,1641.32 466.16,1670.2 C2.1@466.16,1706.73 ; C2.1@465.52,1706.73 465.52,1803.28 R8.1@474.32,1812.07 ; R8.1@473.02,1812.64 R8.1@473.16,1812.51
SCLK/IN2: J10.8 TP15.1 U3.7 | length 2536.5
  Top Layer w12.83: v1(3971.93,1623.8) 4010.31,1623.8 4029.07,1605.04 4098.18,1605.04 U3.7@4098.72,1604.5
  Mid-Layer 1 w19.68: J10.8@1918.99,1628.64 1921.41,1626.22 2191.54,1626.22 TP15.1@2192.81,1627.49
  Bottom Layer w29.53: J10.8@1918.99,1628.64 3770.57,1628.64 3861.5,1537.71 3885.97,1537.71 3971.93,1623.67 v1(3971.93,1623.8)
SDI/IN1: J10.6 TP13.1 U3.6 | length 2419.5
  Top Layer w12.83: v1(3869.95,1606.97) 3914.2,1651.22 4009.52,1651.22 4036.02,1624.72 4110.41,1624.72 U3.6@4110.5,1624.63
  Mid-Layer 1 w19.68: J10.6@1918.99,1728.64 1921.3,1726.33 2060.63,1726.33 TP13.1@2064.64,1730.34
  Bottom Layer w29.53: J10.6@1918.99,1728.64 3745.3,1728.64 3866.96,1606.97 v1(3869.95,1606.97)
SDO/IN4: J10.12 R74.1 TP14.1 U3.9 | length 2916.2
  Top Layer w12.83: R74.1@3782.47,1736.03 3782.47,1590.57 3829.05,1543.99 v1(4006.01,1543.99) 4010.66,1543.99 4030.98,1564.31 U3.9@4072.57,1564.31
  Mid-Layer 1 w19.68: J10.12@1918.99,1428.64 1923.01,1424.62 2185.06,1424.62 TP14.1@2186.28,1423.4
  Bottom Layer w29.53: J10.12@1918.99,1428.64 2404.19,1428.64 2462.97,1369.86 3831.89,1369.86 v1(4006.01,1543.99)
SDO_Pullup: R74.2 U1.54 | length 3099.7
  Top Layer w12.83: U1.54@1126.46,1860.79 1126.6,1860.93 1235.82,1860.93 v1(1235.96,1861.07)
  Top Layer w19.68: v1(3543.39,1803.88) 3544.22,1803.05 3777.2,1803.05 R74.2@3780.89,1799.37
  Mid-Layer 1 w19.68: v1(1380.42,2093.81) 3541.71,2093.81 v1(3543.39,2095.49)
  Mid-Layer 2 w12.83: v1(1235.96,1861.07) 1307.43,1932.54 1312.23,1932.54 1380.42,2000.73 v1(1380.42,2093.81)
  Mid-Layer 2 w19.68: v1(3543.39,1803.88) v1(3543.39,2095.49)
SRC1: R68.1 R70.2 TP27.1 U3.1 | length 726.3
  Top Layer w12.83: U3.1@4094.69,1721.79 4073.08,1721.79 4060.05,1734.81 4060.05,1738.35 4084.94,1763.24 4099.7,1763.24 v1@4104.18,1767.73
  Top Layer w19.68: R68.1@3723.2,2090.21 3724.18,2090.21 3787.18,2027.21 3863.4,2027.21 3932.37,1958.25 R70.2@3933.62,1958.25
  Top Layer w59.06: R70.2@3929.04,1957.23 3938.54,1947.73 4052.4,1947.73 TP27.1@4056.41,1943.72 ; TP27.1@4056.41,1940.77 TP27.1@4087.67,1940.77
  Mid-Layer 2 w78.74: TP27.1@4056.41,1943.72 4056.65,1943.48 4056.65,1814.45 v1(4104.57,1766.53)
SRC1_ADC_MCU: pad.7@3799.96,2158.3 U1.14 U5.1 | length 3226.1
  Top Layer w12.83: U1.14@793.79,2134.41 794.3,2133.9 794.3,2093.07 v2(854.74,2032.63) ; pad.7@3793.07,2156.89 3798.54,2156.89 pad.7@3799.96,2158.3 3813.22,2171.57 3813.22,2173.99 3828.73,2189.5 U5.1@3861.17,2189.5
  Mid-Layer 1 w19.68: v2(854.74,2032.63) 873.92,2013.44 1353.17,2013.44
  Mid-Layer 1 w29.53: v2@853.07,2035.06 v2@855.12,2033.01 ; 1353.17,2013.44 1397.81,2013.44 1432.71,2048.35 3690,2048.35 pad.7@3799.96,2158.3
SRC1_IN_N: C35.2 R69.2 U5.4 | length 164.3
  Top Layer w9.84: C35.2@3918.24,2090.28 3917.25,2090.28 3903.47,2104.06 3903.47,2105.73 3899.39,2109.82 3899.39,2143.38 3905.15,2149.15 3923.23,2149.15 U5.4@3923.29,2149.21
  Top Layer w12.83: C35.2@3918.45,2091.21 3989.78,2091.21 R69.2@3993.44,2087.56
SRC1_IN_P: C35.1 R68.2 U5.3 | length 145.7
  Top Layer w12.83: R68.2@3786.19,2090.21 3786.58,2090.61 C35.1@3853.93,2090.61 ; C35.1@3855.25,2091 3856.96,2091 3868.51,2102.56 3868.51,2104.27 3875.1,2110.85 3875.1,2142.47 3867.95,2149.62 3867.43,2150.13 U5.3@3861.17,2150.13
SRC2: R60.1 R62.2 TP24.1 U3.2 | length 1290.5
  Top Layer w12.83: v1@3999.2,1734.11 3999.2,1732.23 4029.33,1702.1 U3.2@4094.69,1702.1
  Top Layer w19.68: R60.1@3711.5,2594.42 3713.56,2594.42 3783.18,2524.81 3853,2524.81 3922.56,2455.25 R62.2@3922.56,2448.16
  Top Layer w59.06: 3942.43,2433.69 TP24.1@4076.86,2433.69
  Mid-Layer 2 w78.74: v1(3997.57,1733.86) 3951.1,1780.33 3951.1,2307.93 4067.63,2424.46 TP24.1@4067.63,2436.75
SRC2_ADC_MCU: pad.7@3773.88,2670.35 U1.15 U6.1 | length 3815.3
  Top Layer w12.83: v2(762.09,2193.62) 762.09,2191.68 773.59,2180.19 773.59,2134.92 U1.15@774.1,2134.41 ; pad.7@3772.25,2671.45 3774.98,2671.45 3798.43,2694.9 U6.1@3849.79,2694.9
  Mid-Layer 1 w29.53: v2@760.64,2196.6 760.64,2234.95 795.8,2270.11 1090.16,2270.11 v1(1091.79,2268.48) ; v1(1093.07,2739.99) 1143.4,2790.31 v1(3735.37,2790.31)
  Mid-Layer 2 w29.53: v1(1091.79,2268.48) 1093.07,2269.75 v1(1093.07,2739.99) ; v1(3735.37,2790.31) 3749,2790.31 3773.88,2765.43 pad.7@3773.88,2670.35
SRC2_IN_N: C31.2 R61.2 U6.4 | length 124.9
  Top Layer w12.83: C31.2@3907.6,2596.43 U6.4@3907.6,2652.07 ; C31.2@3907.69,2596.43 3910.67,2593.45 R61.2@3975.7,2593.45
SRC2_IN_P: C31.1 R60.2 U6.3 | length 132.9
  Top Layer w12.83: R60.2@3776.61,2593.39 C31.1@3842.56,2593.42 ; C31.1@3844.61,2593.45 3844.61,2646.27 U6.3@3854.56,2656.23
SRC3: R65.1 R67.2 TP28.1 U3.24 | length 1123.9
  Top Layer w12.83: v1@4199.18,1775 4201.25,1772.92 v1(4203.49,1772.92) 4266.46,1772.92 4289.32,1750.07 4289.32,1722.3 4288.8,1721.79 U3.24@4267.92,1721.79
  Top Layer w29.53: R65.1@4333.47,2592.62 4333.47,2466.41 4346.3,2453.57 TP28.1@4346.3,2438.08
  Top Layer w59.06: TP28.1@4352.73,2441.51 4431.57,2441.51 R67.2@4448.17,2458.11
  Mid-Layer 2 w78.74: 4204.04,2294.04 TP28.1@4346.14,2436.14 ; v1@4204.64,1784.04 4204.94,2294.94
SRC3_ADC_MCU: pad.7@4416.63,2665.76 U1.16 U7.1 | length 4447.8
  Top Layer w12.83: U1.16@754.42,2134.41 754.42,2078.12 766.91,2065.62 v2(767.66,2065.62) v2@767.66,2065.1 ; pad.7@4415.46,2669.07 4419.94,2669.07 4429.89,2679.03 4429.89,2682.86 4438.95,2691.91 U7.1@4471.39,2691.91
  Mid-Layer 1 w12.83: v2(767.66,2065.62) 797.77,2095.74 v1(1128.15,2095.74)
  Mid-Layer 1 w29.53: v1(1204.43,2733.52) 4386.98,2733.52 4414.2,2706.29 4414.2,2668.18 pad.7@4416.63,2665.76
  Mid-Layer 2 w29.53: v1(1128.15,2095.74) 1150.93,2118.51 1150.93,2680.02 v1(1204.43,2733.52)
SRC3_IN_N: C33.2 R66.2 U7.4 | length 133.7
  Top Layer w12.83: U7.4@4525.61,2651.43 4527.1,2649.94 C33.2@4527.1,2592.62 ; C33.2@4527.1,2592.62 4597.17,2592.65 R66.2@4600.09,2595.57
SRC3_IN_P: C33.1 R65.2 U7.3 | length 127.3
  Top Layer w12.83: R65.2@4396.46,2592.62 C33.1@4464.11,2592.62 4464.11,2651.52 U7.3@4464.61,2652.03
SRC4: R71.1 R73.2 TP29.1 U3.23 | length 580.9
  Top Layer w12.83: U3.23@4267.92,1702.1 4317.29,1702.1 4344.85,1729.66 v2@4347.35,1729.66
  Top Layer w19.68: R71.1@4325.65,2100.2 4329.2,2100.2 4337.72,2091.67 4337.72,2082.23 4451.26,1968.69 R73.2@4451.26,1961.6
  Top Layer w59.06: TP29.1@4354.75,1944.92 4358.76,1948.93 R73.2@4434.74,1948.93
  Mid-Layer 2 w78.74: v2(4345.69,1730.5) 4345.69,1929.24 TP29.1@4357.67,1941.22
SRC4_ADC_MCU: pad.3 U1.19 U8.1 | length 3931.7
  Top Layer w12.83: U1.19@677.64,2018.27 752.12,2018.27 v2(773.43,1996.96) ; pad.3@4394.87,2163.16 4396.65,2163.16 pad.3@4398.45,2164.95 4411.72,2178.22 4411.72,2180 4433.76,2202.04 U8.1@4460.57,2202.04
  Mid-Layer 1 w19.68: v2@769.47,1995.29 769.47,1997.24 822.44,1944.27 1378.88,1944.27 1447.43,2012.82
  Mid-Layer 1 w29.53: 1447.43,2012.82 4246.32,2012.82 pad.3@4398.45,2164.95
SRC4_IN_N: C37.2 R72.2 U8.4 | length 136.7
  Top Layer w12.83: U8.4@4518.83,2162.67 4518.83,2104.52 C37.2@4519.3,2104.05 ; C37.2@4522.53,2100.6 R72.2@4592.41,2100.6 4598.59,2100.6 R72.2@4599.88,2101.89
SRC4_IN_P: C37.1 R71.2 U8.3 | length 127.5
  Top Layer w12.83: R71.2@4390.9,2100.56 C37.1@4455.4,2100.56 ; C37.1@4455.4,2101.89 4460.57,2107.05 U8.3@4460.57,2162.67
SWCLK: J11.14 U1.13 | length 1197.1
  Top Layer w8: v5(795.96,1530) 795.96,1477.38 867.87,1405.48 867.87,1340.59 901.24,1307.21 937.99,1307.21 975.13,1344.36 1010.08,1344.36 J11.14@1018.44,1352.72 ; v5(811.31,2193.62) 812.39,2192.54 812.39,2135.49 U1.13@813.47,2134.41
  Bottom Layer w8: v5(795.96,1530) 795.96,1534.33 819.61,1557.98 819.61,1705.19 886.63,1772.2 886.63,1951.94 808.62,2029.95 808.62,2190.93 v5(811.31,2193.62)
SWDIO: J11.12 U1.12 | length 1002.1
  Top Layer w6: v5(829.66,1534.33) 829.66,1486.28 858.46,1457.49 875.97,1457.49 919.61,1413.84 919.61,1353.9 J11.12@918.44,1352.72 ; U1.12@833.16,2134.41 833.23,2134.48 833.23,2172.94 843.54,2183.25 v5(843.54,2187.05)
  Bottom Layer w6: v5(829.66,1534.33) 829.66,1538.92 837.58,1546.84 837.58,1699.67 904.23,1766.32 906.23,1766.32 906.23,2023.67 850.33,2079.56 843.54,2079.56 v5(843.54,2187.05)
UART1_RX: J11.6 U1.53 | length 959.1
  Top Layer w12.83: v11(1012.38,1871.15) 1047.91,1871.15 1077.97,1841.1 U1.53@1126.46,1841.1
  Mid-Layer 1 w12.83: v11(618.14,1684.32) 619.33,1685.51 619.61,1685.51 805.26,1871.15 v11(1012.38,1871.15)
  Mid-Layer 2 w12.83: v11(618.14,1684.32) 582.93,1649.11 582.93,1388.25 J11.6@618.44,1352.72
UART1_TX: J11.8 U1.52 | length 920.8
  Top Layer w6: v4(1047.72,1826.2) 1050.11,1823.81 1124.07,1823.81 U1.52@1126.46,1821.42
  Mid-Layer 1 w12.6: v11(762.13,1790.71) 801.6,1830.18 920.31,1830.18 924.29,1826.2 v4(1047.72,1826.2)
  Mid-Layer 2 w12.6: J11.8@718.44,1352.72 719.61,1353.9 719.61,1425.73 622.6,1522.74 622.6,1651.19 v11(762.13,1790.71)
USB_5V: C21.1 L3.1 U2.4 U2.5 U2.6 USB1.A4-B9 USB1.A9-B4 | length 1090
  Top Layer w12: v2(163.96,889.54) 169.86,895.45 235.53,895.45 USB1.A4-B9@241.04,900.95
  Top Layer w12.83: 143.4,417.11 143.78,416.73 ; U2.4@146.2,393.25 146.2,414.31 143.78,416.73 ; 171.04,415.96 189.43,415.96 196.95,408.44 196.95,393.68 U2.6@197.39,393.25 ; 171.04,416.73 143.78,416.73 ; U2.5@171.8,393.25 172.23,393.68 172.23,412.74 ; 178.01,722.48 205.89,722.48 210.99,717.37 235.64,717.37 USB1.A9-B4@241.04,711.97
  Top Layer w19.68: 140.41,417.11 140.41,557 163.06,579.64 ; 178.01,722.48 154.23,698.69 154.23,636.37 v6(116.5,598.65) 118.48,596.67 146.03,596.67 163.06,579.64 ; L3.1@256.06,526.06 C21.1@177.25,526.06 177.25,565.46 163.06,579.64
  Bottom Layer w29.53: v6(116.5,598.65) 116.5,842.09 v2(163.96,889.54)
VBUS_DETECT: R29.2 R30.2 XDS1.1 | length 170
  Top Layer w8: XDS1.1@1220.76,546.47 1245.01,546.47 1260.01,531.47 R29.2@1324.56,531.47 R30.2@1324.56,471.51
VCLAMP: J7.1 J8.1 U3.4 U3.21 | length 2140.3
  Top Layer w12.83: v1@3926.95,1700.1 3927.45,1700.6 3991.52,1700.6 4029.39,1662.73 U3.4@4094.69,1662.73 ; U3.21@4267.92,1662.73 4366.49,1662.73 4403.03,1699.27 v1@4403.03,1701.73 ; v1@4404.26,1700.5 v1(4404.53,1700.78)
  Mid-Layer 1 w78.74: J8.1@3484.24,1558.7 J8.1@3484.34,1558.63 ; J8.1@3484.34,1558.63 3495.13,1569.42 J8.1@3495.13,1576.61 ; 3596.36,1677.83 3908.21,1677.83 v1(3929.47,1699.09) 3929.47,1717.33 3928.37,1718.42 3928.37,1783.66 3985.52,1840.8 4010.17,1840.8 4011.22,1841.85 4350.52,1841.85 4404.53,1787.83 v1(4404.53,1700.78)
  Mid-Layer 1 w98.43: J7.1@2883.02,1558.7 J8.1@3484.24,1558.7 ; J8.1@3495.13,1576.61 3596.36,1677.83
VM: C39.1 C40.2 C46.2 C48.2 C49.2 C50.2 D18.2 J1.2 J2.2 J3.2 J4.2 L1.2 R4.2 R51.2 R52.2 R81.2 TP16.1 TP23.1 TP31.1 TP32.1 U3.16 | length 10554.1
  Top Layer w12.83: U3.16@4267.92,1564.31 4268.43,1563.79 4293.39,1563.79 4294.24,1562.94 4300.47,1562.94 4311.68,1551.73 4372.6,1551.73 4395.18,1529.16 ; R81.2@5328.84,271.59 5328.84,338.03 5335.84,345.03
  Top Layer w29.53: R4.2@588.62,2256.56 588.62,2268.39 646.45,2326.22 v10@821.82,2326.22
  Top Layer w59.06: 4395.18,1422.41 4395.18,1529.16 ; D18.2@5417.46,267.87 5417.46,361.34 5417.8,361.68
  Top Layer w100: R51.2@3270.71,1262.13 3271.52,1261.31 R52.2@3415.11,1261.31 ; v1(3331.01,1128.82) 3331.01,1183.84 R52.2@3401.9,1254.72 ; C40.2@4380.2,1389.58 4412.47,1389.58 v1(4414.58,1391.7)
  Mid-Layer 1 w100: v1@4383.49,1388.7 4389.62,1394.83
  Mid-Layer 2 w59.06: TP32.1@5391.27,956.25 TP32.1@5394.16,956.25 TP32.1@5398.83,956.25
  Bottom Layer w39.37: v10(830.49,2335.5) 832.97,2333.01 1189.8,2333.01 1265.81,2257 1436.03,2257 1654.22,2038.8 4480.85,2038.8 4547.81,1971.85 5523.76,1971.85
  Bottom Layer w59.06: TP32.1@5394.16,956.25 5548.12,956.25 5556.55,947.82 ; 5581.02,921.88 J4.2@5719.02,921.88
  Bottom Layer w78.74: TP31.1@5391.99,1507.06 5563.66,1507.06 ; TP23.1@5393.57,2068 5536.72,2068 ; TP16.1@5393.57,2624.2 5532.98,2624.2 ; 5571.71,2589.15 J1.2@5716.76,2589.15 ; 5597.26,1472.68 J3.2@5719.02,1472.68 ; 5605.11,2034.31 J2.2@5716.76,2034.31
  Bottom Layer w100: v1(3331.01,1128.82) 3391.47,1128.82 3394.78,1132.13 5473.4,1132.13 5573.66,1031.87 5573.66,971.25 ; 4389.62,1394.83 5496.81,1394.83 5553.99,1452.01
  other v1: 4374.76,1389.4
  other v6: 5604.78,360.6 5510.32,362.21 5603.18,418.09 5512.33,420.1 5601.97,473.96 5509.11,475.17
VM_IN: C47.2 C51.2 D8.2 J5.1 Q4.1 Q4.2 Q4.3 TP21.1 U4.2 U4.5 | length 687.8
  Top Layer w19.68: U4.2@3590.53,912.81 3609.23,912.81 3773.7,748.34 3773.7,720.03 C51.2@3781.47,712.26
  Top Layer w59.06: C51.2@3781.57,700.46 3904.58,700.46 3910.83,706.71
  Top Layer w100: TP21.1@3689.25,294.92 3946.05,294.92 J5.1@3952.06,288.91
VREF_N: C1.1 R6.2 U1.17 | length 131.5
  Top Layer w6: R6.2@605.93,2079.29 607.41,2077.81 C1.1@607.41,2030.08 618.5,2041.16 633.84,2041.16 645.53,2052.86 649.24,2052.86 654.02,2057.64 U1.17@677.64,2057.64
VREF_P: C1.2 R7.2 U1.24 | length 152.9
  Top Layer w6: R7.2@598.04,1919.84 598.04,1961.65 C1.2@607.41,1971.02 617.71,1960.72 617.71,1949.79 644.75,1922.75 674.74,1922.75 U1.24@677.64,1919.84
XDS_ID: XDS1.95
XDS_RESET_OUT: J11.9 R17.1 XDS1.40 | length 522
  Top Layer w8: v2(1051.86,1141.83) 1099.6,1189.57 1171.22,1189.57 1202.57,1158.22 R17.1@1202.57,1154.29 ; XDS1.40@1051.89,1094.05 v2@1051.89,1141.8
  Bottom Layer w8: J11.9@818.44,1252.72 818.44,1249.68 884.12,1184 1019.33,1184 1050.33,1153.01 1050.33,1143.36 v2(1051.86,1141.83)
XDS_RXD: J11.7 XDS1.33 | length 581.4
  Top Layer w8: XDS1.33@1161.71,1117.28 1161.71,1138.28 1165.61,1142.18 v2(1165.61,1166.57)
  Bottom Layer w8: J11.7@718.44,1252.72 849.33,1121.83 1123.16,1121.83 1165.61,1164.28 v2(1165.61,1166.57) 1163.32,1168.86 v2@1163.32,1174.85
XDS_TCK_SWDCLK: J11.13 XDS1.35 | length 205.2
  Top Layer w8: v2(1120.08,1148.04) 1130.67,1137.45 XDS1.35@1130.67,1094.01
  Bottom Layer w8: J11.13@1018.44,1252.72 1018.44,1249.68 v2(1120.08,1148.04)
XDS_TDI: XDS1.38
XDS_TDO_SWO: XDS1.37
XDS_TMS_SWDIO: J11.11 XDS1.36 | length 280.2
  Top Layer w8: v2(1094.69,1141.83) 1114.86,1121.66 1114.86,1094.08 XDS1.36@1114.92,1094.01
  Bottom Layer w8: J11.11@918.44,1252.72 918.44,1249.68 964.98,1203.14 1033.37,1203.14 v2(1094.69,1141.83)
XDS_TXD: J11.5 XDS1.34 | length 683.7
  Top Layer w8: v2(1139.61,1166.57) 1141.91,1164.27 1141.91,1146.01 1146.41,1141.5 XDS1.34@1146.41,1094.01
  Bottom Layer w8: J11.5@618.44,1252.72 661.9,1296.19 1036.44,1296.19 1139.61,1193.01 v2(1139.61,1166.57)
XDS_USB_D_N: IC2.5 USB1.A7 USB1.B7 XDS1.93 | length 1046.7
  Top Layer w6: XDS1.93@614.46,593.97 638.4,593.97 639.88,595.45 663.08,595.45 664.08,596.45
  Top Layer w8: v6(163.96,808.45) 163.96,813.32 186.62,835.99 USB1.B7@241.04,835.99 ; USB1.A7@241.04,796.62 241.36,796.94 293.57,796.94 ; v4(291.3,755.07) 290.78,755.58 290.78,794.15 293.57,796.94 ; IC2.5@317.35,797.26 317.03,796.94 293.57,796.94 ; 664.08,596.45 664.47,596.45 v3(688.61,620.59)
  Bottom Layer w8: v6(163.96,808.45) 217.34,755.07 v4(291.3,755.07) 355.47,755.07 392.97,792.57 ; 392.98,794.43 670.98,793.57 719.31,745.23 719.31,666.41 697.87,644.97 697.87,629.84 v3(688.61,620.59)
XDS_USB_D_P: IC2.4 USB1.A6 USB1.B6 XDS1.94 | length 975.3
  Top Layer w6: XDS1.94@614.46,577.97 645.02,577.97 646.5,579.45 663.08,579.45 664.08,578.45
  Top Layer w8: USB1.B6@241.04,776.93 201.33,776.93 194.29,783.97 194.29,802.99 207.61,816.3 USB1.A6@241.04,816.3 241.36,816.62 293.08,816.62 ; v4(296.07,847.06) 296.07,819.61 293.08,816.62 ; IC2.4@317.35,816.95 317.03,816.62 293.08,816.62 ; 664.08,578.45 682.8,578.45 v3(706.78,602.43)
  Bottom Layer w8: v4(296.07,847.06) 357.63,847.06 392.25,812.43 ; 392.26,810.57 678.43,811.57 737.31,752.69 737.31,658.96 715.87,637.51 715.87,611.52 v3(706.78,602.43)
XDS_VBUS: C13.1 C14.1 C22.1 IC1.5 IC1.8 IC2.6 J11.1 L3.2 R24.1 R29.1 | length 2775.1
  Top Layer w10: v2(1370.61,500.57) 1370.61,530.28 R29.1@1371.81,531.47
  Top Layer w12.83: C13.1@189.03,1118.91 220.1,1118.91 248.53,1147.34 IC1.5@261.47,1147.34 ; v10(200.11,1066.2) 265.51,1066.2 IC1.8@269.55,1070.24 ; IC2.6@317.35,777.58 317.35,716.08 324.22,709.2 v12@324.22,707.69 ; v6(495.87,481.52) 495.87,480.78 495.87,381.7 508.23,369.34 510.04,369.34 519.5,359.88 R24.1@519.5,346.24
  Top Layer w20: J11.1@417.28,1251.57 J11.1@418.44,1252.72
  Top Layer w29.53: C13.1@191.99,1117.93 191.99,1074.33 v10(200.11,1066.2)
  Top Layer w39.37: L3.2@256.06,463.07 273.68,480.69 285.4,480.69 285.48,480.78 v6@495.87,480.78 ; v12(325.3,705.11) 354.05,705.11 392.27,743.32 v12@392.27,937.12
  Bottom Layer w19.68: v6(495.87,481.52) 559.71,481.52 637.51,403.73 1070.78,403.73 1167.61,500.57 v2(1370.61,500.57)
  Bottom Layer w29.53: v10(200.11,1066.2) 216.66,1049.65 418.44,1049.65 ; v12(392.62,940.89) 418.44,966.71 418.44,1049.65 ; J11.1@418.44,1252.72 418.44,1049.65
  Bottom Layer w39.37: v12(325.3,705.11) 325.3,652.09 v6(495.87,481.52)
XDS_VCC: C9.1 C10.1 C11.1 C15.1 C19.1 C20.1 C25.1 C26.1 C30.2 IC1.1 J11.3 R14.2 R17.2 R18.2 R19.2 R20.2 R21.2 R22.2 R25.1 R26.1 R28.2 TP7.1 XDS1.7 XDS1.8 XDS1.16 XDS1.26 XDS1.28 XDS1.39 XDS1.47 XDS1.51 XDS1.52 XDS1.69 XDS1.79 XDS1.90 XDS1.101 XDS1.113 XDS1.122 | length 1402.9
  Top Layer w8: C15.1@532.62,857.18 C15.1@536.56,857.18 ; 544.37,831.81 561.7,814.49 XDS1.79@614.92,814.49 ; C15.1@544.37,849.37 C15.1@536.56,857.18 ; C15.1@544.37,864.99 C15.1@536.56,857.18 ; 558.37,869.68 558.37,966.98 563.05,971.67 XDS1.69@590.91,971.67 ; XDS1.90@614.46,640.96 642.05,640.96 652.66,651.57 710.61,651.57 736.51,625.67 XDS1.101@736.51,487.42 736.51,450.67 766.1,421.08 766.1,406.61 C25.1@773.12,399.58 ; C9.1@824.49,1160.69 832.3,1152.88 858.2,1152.88 862.89,1148.19 862.89,1094.08 XDS1.52@862.95,1094.01 ; XDS1.47@941.24,1093.72 941.24,1153.02 C10.1@943.19,1154.97 ; XDS1.8@1193.57,657.07 1221.15,657.07 XDS1.8@1221.22,657.01 ; XDS1.16@1193.57,782.93 1244.62,782.93 1244.75,783.05 1273.08,783.05 1279.11,789.09 1279.11,1013.49 ; R17.2@1197.57,1196.53 R17.2@1202.57,1201.53 ; XDS1.7@1221.15,641.19 XDS1.7@1221.22,641.26 ; XDS1.26@1221.22,940.47 1244.68,940.47 1244.75,940.53 1279.11,940.53 ; v2(1301.61,630.57) 1301.61,632.38 1320.63,651.39 C19.1@1324.56,651.39 ; C11.1@1317.17,1051.55 C11.1@1321.11,1051.55 ; R18.2@1321.57,1238.25 R19.2@1321.57,1177.91 R20.2@1321.57,1117.57 R20.2@1325.51,1117.57
  Top Layer w20: R26.1@709.08,352.34 709.08,356.27 710.89,358.08 728.69,358.08 ; C25.1@773.12,395.64 C25.1@773.12,399.58
  Bottom Layer w8: TP7.1@1300.61,596.57 1301.11,597.07 1301.11,630.07 v2(1301.61,630.57)
pads on no net: FID1.1 FID2.1 FID3.1 IC1.2 IC1.3 IC1.6 IC1.7 IC2.1 IC2.2 IC3.2 IC3.4 IC3.5 J6.2 Q4.9@3885.78,945.59 Q4.9@3926.82,957.21 Q4.9@3926.82,1002.48 Q4.9@3926.82,1047.76 Q4.9@3979.19,957.21 Q4.9@3979.19,1002.48 Q4.9@3979.19,1007.8 Q4.9@3979.19,1047.76 Q4.9@4031.55,957.21 Q4.9@4031.55,1002.48 Q4.9@4031.55,1047.76 Q4.9@4072.59,945.59 SH-J1.0 SH-J2.0 SH-J3.0 SH-J4.0 SH-J5.0 SH-J6.0 SH-J7.0 SH-J8.0 SH-J9.0 SH-J10.0 SH-J11.0 SH-J12.0 SH-J14.0 SH-J15.0 SH-J16.0 SH-J17.0 SH-J18.0 SH-J19.0 SH-J20.0 U1.2 U1.3 U1.5 U1.6 U1.7 U1.18 U1.20 U1.21 U1.22 U1.25 U1.28 U1.29 U1.31 U1.39 U1.42 U1.44 U1.55 U1.56 U1.57 U1.61 U2.7@154.08,354.86 U2.7@189.51,354.86 U3.3 U3.5 U3.15 U3.22 U4.3 U4.7 USB1. USB1.A8 USB1.B8 XDS1.2 XDS1.5 XDS1.6 XDS1.11 XDS1.12 XDS1.13 XDS1.14 XDS1.15 XDS1.18 XDS1.19 XDS1.20 XDS1.21 XDS1.22 XDS1.23 XDS1.24 XDS1.25 XDS1.27 XDS1.29 XDS1.30 XDS1.31 XDS1.32 XDS1.41 XDS1.43 XDS1.44 XDS1.45 XDS1.46 XDS1.49 XDS1.50 XDS1.53 XDS1.54 XDS1.56 XDS1.57 XDS1.65 XDS1.67 XDS1.71 XDS1.72 XDS1.73 XDS1.74 XDS1.75 XDS1.76 XDS1.77 XDS1.78 XDS1.81 XDS1.82 XDS1.83 XDS1.84 XDS1.85 XDS1.86 XDS1.91 XDS1.92 XDS1.102 XDS1.103 XDS1.104 XDS1.105 XDS1.106 XDS1.107 XDS1.108 XDS1.109 XDS1.110 XDS1.111 XDS1.112 XDS1.116 XDS1.117 XDS1.118 XDS1.119 XDS1.121 XDS1.123 XDS1.124 XDS1.125 XDS1.126 XDS1.127 XDS1.128
copper on no net:
  other v2: 659.61,555.57 658.61,624.57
